VERSION 5.7 ;
BUSBITCHARS "[]" ;
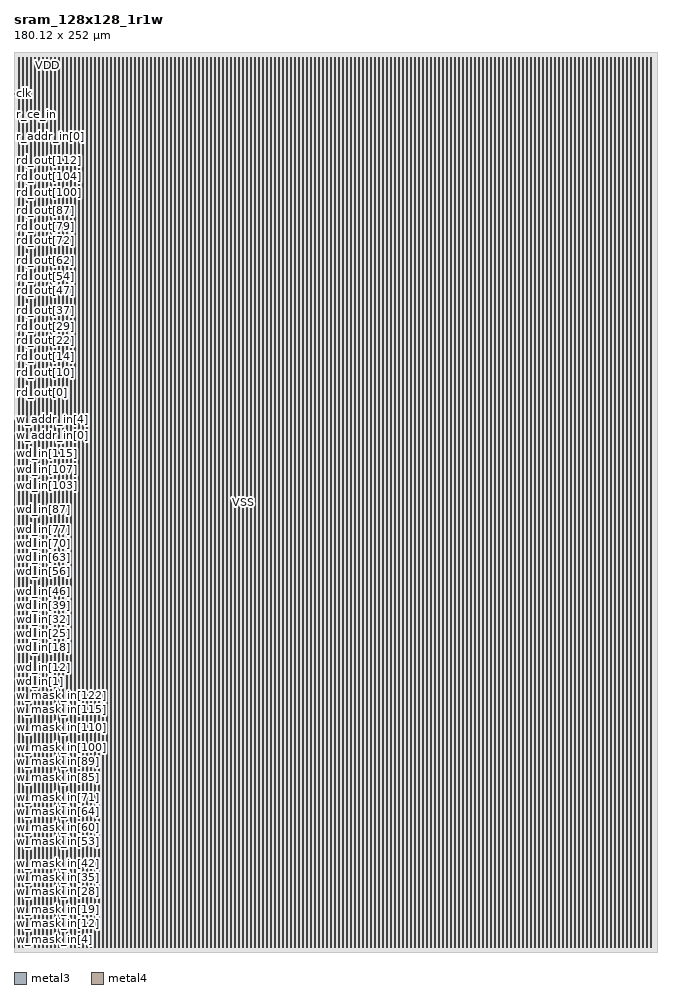
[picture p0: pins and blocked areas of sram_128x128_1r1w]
MACRO sram_128x128_1r1w
  FOREIGN sram_128x128_1r1w 0 0 ;
  SYMMETRY X Y R90 ;
  SIZE 180.120 BY 252.000 ;
  CLASS BLOCK ;
  PIN w_mask_in[0]
    DIRECTION INPUT ;
    USE SIGNAL ;
    SHAPE ABUTMENT ;
    PORT
      LAYER metal3 ;
      RECT 0.000 1.365 0.070 1.435 ;
    END
  END w_mask_in[0]
  PIN w_mask_in[1]
    DIRECTION INPUT ;
    USE SIGNAL ;
    SHAPE ABUTMENT ;
    PORT
      LAYER metal3 ;
      RECT 0.000 1.925 0.070 1.995 ;
    END
  END w_mask_in[1]
  PIN w_mask_in[2]
    DIRECTION INPUT ;
    USE SIGNAL ;
    SHAPE ABUTMENT ;
    PORT
      LAYER metal3 ;
      RECT 0.000 2.485 0.070 2.555 ;
    END
  END w_mask_in[2]
  PIN w_mask_in[3]
    DIRECTION INPUT ;
    USE SIGNAL ;
    SHAPE ABUTMENT ;
    PORT
      LAYER metal3 ;
      RECT 0.000 3.045 0.070 3.115 ;
    END
  END w_mask_in[3]
  PIN w_mask_in[4]
    DIRECTION INPUT ;
    USE SIGNAL ;
    SHAPE ABUTMENT ;
    PORT
      LAYER metal3 ;
      RECT 0.000 3.605 0.070 3.675 ;
    END
  END w_mask_in[4]
  PIN w_mask_in[5]
    DIRECTION INPUT ;
    USE SIGNAL ;
    SHAPE ABUTMENT ;
    PORT
      LAYER metal3 ;
      RECT 0.000 4.165 0.070 4.235 ;
    END
  END w_mask_in[5]
  PIN w_mask_in[6]
    DIRECTION INPUT ;
    USE SIGNAL ;
    SHAPE ABUTMENT ;
    PORT
      LAYER metal3 ;
      RECT 0.000 4.725 0.070 4.795 ;
    END
  END w_mask_in[6]
  PIN w_mask_in[7]
    DIRECTION INPUT ;
    USE SIGNAL ;
    SHAPE ABUTMENT ;
    PORT
      LAYER metal3 ;
      RECT 0.000 5.285 0.070 5.355 ;
    END
  END w_mask_in[7]
  PIN w_mask_in[8]
    DIRECTION INPUT ;
    USE SIGNAL ;
    SHAPE ABUTMENT ;
    PORT
      LAYER metal3 ;
      RECT 0.000 5.845 0.070 5.915 ;
    END
  END w_mask_in[8]
  PIN w_mask_in[9]
    DIRECTION INPUT ;
    USE SIGNAL ;
    SHAPE ABUTMENT ;
    PORT
      LAYER metal3 ;
      RECT 0.000 6.405 0.070 6.475 ;
    END
  END w_mask_in[9]
  PIN w_mask_in[10]
    DIRECTION INPUT ;
    USE SIGNAL ;
    SHAPE ABUTMENT ;
    PORT
      LAYER metal3 ;
      RECT 0.000 6.965 0.070 7.035 ;
    END
  END w_mask_in[10]
  PIN w_mask_in[11]
    DIRECTION INPUT ;
    USE SIGNAL ;
    SHAPE ABUTMENT ;
    PORT
      LAYER metal3 ;
      RECT 0.000 7.525 0.070 7.595 ;
    END
  END w_mask_in[11]
  PIN w_mask_in[12]
    DIRECTION INPUT ;
    USE SIGNAL ;
    SHAPE ABUTMENT ;
    PORT
      LAYER metal3 ;
      RECT 0.000 8.085 0.070 8.155 ;
    END
  END w_mask_in[12]
  PIN w_mask_in[13]
    DIRECTION INPUT ;
    USE SIGNAL ;
    SHAPE ABUTMENT ;
    PORT
      LAYER metal3 ;
      RECT 0.000 8.645 0.070 8.715 ;
    END
  END w_mask_in[13]
  PIN w_mask_in[14]
    DIRECTION INPUT ;
    USE SIGNAL ;
    SHAPE ABUTMENT ;
    PORT
      LAYER metal3 ;
      RECT 0.000 9.205 0.070 9.275 ;
    END
  END w_mask_in[14]
  PIN w_mask_in[15]
    DIRECTION INPUT ;
    USE SIGNAL ;
    SHAPE ABUTMENT ;
    PORT
      LAYER metal3 ;
      RECT 0.000 9.765 0.070 9.835 ;
    END
  END w_mask_in[15]
  PIN w_mask_in[16]
    DIRECTION INPUT ;
    USE SIGNAL ;
    SHAPE ABUTMENT ;
    PORT
      LAYER metal3 ;
      RECT 0.000 10.325 0.070 10.395 ;
    END
  END w_mask_in[16]
  PIN w_mask_in[17]
    DIRECTION INPUT ;
    USE SIGNAL ;
    SHAPE ABUTMENT ;
    PORT
      LAYER metal3 ;
      RECT 0.000 10.885 0.070 10.955 ;
    END
  END w_mask_in[17]
  PIN w_mask_in[18]
    DIRECTION INPUT ;
    USE SIGNAL ;
    SHAPE ABUTMENT ;
    PORT
      LAYER metal3 ;
      RECT 0.000 11.445 0.070 11.515 ;
    END
  END w_mask_in[18]
  PIN w_mask_in[19]
    DIRECTION INPUT ;
    USE SIGNAL ;
    SHAPE ABUTMENT ;
    PORT
      LAYER metal3 ;
      RECT 0.000 12.005 0.070 12.075 ;
    END
  END w_mask_in[19]
  PIN w_mask_in[20]
    DIRECTION INPUT ;
    USE SIGNAL ;
    SHAPE ABUTMENT ;
    PORT
      LAYER metal3 ;
      RECT 0.000 12.565 0.070 12.635 ;
    END
  END w_mask_in[20]
  PIN w_mask_in[21]
    DIRECTION INPUT ;
    USE SIGNAL ;
    SHAPE ABUTMENT ;
    PORT
      LAYER metal3 ;
      RECT 0.000 13.125 0.070 13.195 ;
    END
  END w_mask_in[21]
  PIN w_mask_in[22]
    DIRECTION INPUT ;
    USE SIGNAL ;
    SHAPE ABUTMENT ;
    PORT
      LAYER metal3 ;
      RECT 0.000 13.685 0.070 13.755 ;
    END
  END w_mask_in[22]
  PIN w_mask_in[23]
    DIRECTION INPUT ;
    USE SIGNAL ;
    SHAPE ABUTMENT ;
    PORT
      LAYER metal3 ;
      RECT 0.000 14.245 0.070 14.315 ;
    END
  END w_mask_in[23]
  PIN w_mask_in[24]
    DIRECTION INPUT ;
    USE SIGNAL ;
    SHAPE ABUTMENT ;
    PORT
      LAYER metal3 ;
      RECT 0.000 14.805 0.070 14.875 ;
    END
  END w_mask_in[24]
  PIN w_mask_in[25]
    DIRECTION INPUT ;
    USE SIGNAL ;
    SHAPE ABUTMENT ;
    PORT
      LAYER metal3 ;
      RECT 0.000 15.365 0.070 15.435 ;
    END
  END w_mask_in[25]
  PIN w_mask_in[26]
    DIRECTION INPUT ;
    USE SIGNAL ;
    SHAPE ABUTMENT ;
    PORT
      LAYER metal3 ;
      RECT 0.000 15.925 0.070 15.995 ;
    END
  END w_mask_in[26]
  PIN w_mask_in[27]
    DIRECTION INPUT ;
    USE SIGNAL ;
    SHAPE ABUTMENT ;
    PORT
      LAYER metal3 ;
      RECT 0.000 16.485 0.070 16.555 ;
    END
  END w_mask_in[27]
  PIN w_mask_in[28]
    DIRECTION INPUT ;
    USE SIGNAL ;
    SHAPE ABUTMENT ;
    PORT
      LAYER metal3 ;
      RECT 0.000 17.045 0.070 17.115 ;
    END
  END w_mask_in[28]
  PIN w_mask_in[29]
    DIRECTION INPUT ;
    USE SIGNAL ;
    SHAPE ABUTMENT ;
    PORT
      LAYER metal3 ;
      RECT 0.000 17.605 0.070 17.675 ;
    END
  END w_mask_in[29]
  PIN w_mask_in[30]
    DIRECTION INPUT ;
    USE SIGNAL ;
    SHAPE ABUTMENT ;
    PORT
      LAYER metal3 ;
      RECT 0.000 18.165 0.070 18.235 ;
    END
  END w_mask_in[30]
  PIN w_mask_in[31]
    DIRECTION INPUT ;
    USE SIGNAL ;
    SHAPE ABUTMENT ;
    PORT
      LAYER metal3 ;
      RECT 0.000 18.725 0.070 18.795 ;
    END
  END w_mask_in[31]
  PIN w_mask_in[32]
    DIRECTION INPUT ;
    USE SIGNAL ;
    SHAPE ABUTMENT ;
    PORT
      LAYER metal3 ;
      RECT 0.000 19.285 0.070 19.355 ;
    END
  END w_mask_in[32]
  PIN w_mask_in[33]
    DIRECTION INPUT ;
    USE SIGNAL ;
    SHAPE ABUTMENT ;
    PORT
      LAYER metal3 ;
      RECT 0.000 19.845 0.070 19.915 ;
    END
  END w_mask_in[33]
  PIN w_mask_in[34]
    DIRECTION INPUT ;
    USE SIGNAL ;
    SHAPE ABUTMENT ;
    PORT
      LAYER metal3 ;
      RECT 0.000 20.405 0.070 20.475 ;
    END
  END w_mask_in[34]
  PIN w_mask_in[35]
    DIRECTION INPUT ;
    USE SIGNAL ;
    SHAPE ABUTMENT ;
    PORT
      LAYER metal3 ;
      RECT 0.000 20.965 0.070 21.035 ;
    END
  END w_mask_in[35]
  PIN w_mask_in[36]
    DIRECTION INPUT ;
    USE SIGNAL ;
    SHAPE ABUTMENT ;
    PORT
      LAYER metal3 ;
      RECT 0.000 21.525 0.070 21.595 ;
    END
  END w_mask_in[36]
  PIN w_mask_in[37]
    DIRECTION INPUT ;
    USE SIGNAL ;
    SHAPE ABUTMENT ;
    PORT
      LAYER metal3 ;
      RECT 0.000 22.085 0.070 22.155 ;
    END
  END w_mask_in[37]
  PIN w_mask_in[38]
    DIRECTION INPUT ;
    USE SIGNAL ;
    SHAPE ABUTMENT ;
    PORT
      LAYER metal3 ;
      RECT 0.000 22.645 0.070 22.715 ;
    END
  END w_mask_in[38]
  PIN w_mask_in[39]
    DIRECTION INPUT ;
    USE SIGNAL ;
    SHAPE ABUTMENT ;
    PORT
      LAYER metal3 ;
      RECT 0.000 23.205 0.070 23.275 ;
    END
  END w_mask_in[39]
  PIN w_mask_in[40]
    DIRECTION INPUT ;
    USE SIGNAL ;
    SHAPE ABUTMENT ;
    PORT
      LAYER metal3 ;
      RECT 0.000 23.765 0.070 23.835 ;
    END
  END w_mask_in[40]
  PIN w_mask_in[41]
    DIRECTION INPUT ;
    USE SIGNAL ;
    SHAPE ABUTMENT ;
    PORT
      LAYER metal3 ;
      RECT 0.000 24.325 0.070 24.395 ;
    END
  END w_mask_in[41]
  PIN w_mask_in[42]
    DIRECTION INPUT ;
    USE SIGNAL ;
    SHAPE ABUTMENT ;
    PORT
      LAYER metal3 ;
      RECT 0.000 24.885 0.070 24.955 ;
    END
  END w_mask_in[42]
  PIN w_mask_in[43]
    DIRECTION INPUT ;
    USE SIGNAL ;
    SHAPE ABUTMENT ;
    PORT
      LAYER metal3 ;
      RECT 0.000 25.445 0.070 25.515 ;
    END
  END w_mask_in[43]
  PIN w_mask_in[44]
    DIRECTION INPUT ;
    USE SIGNAL ;
    SHAPE ABUTMENT ;
    PORT
      LAYER metal3 ;
      RECT 0.000 26.005 0.070 26.075 ;
    END
  END w_mask_in[44]
  PIN w_mask_in[45]
    DIRECTION INPUT ;
    USE SIGNAL ;
    SHAPE ABUTMENT ;
    PORT
      LAYER metal3 ;
      RECT 0.000 26.565 0.070 26.635 ;
    END
  END w_mask_in[45]
  PIN w_mask_in[46]
    DIRECTION INPUT ;
    USE SIGNAL ;
    SHAPE ABUTMENT ;
    PORT
      LAYER metal3 ;
      RECT 0.000 27.125 0.070 27.195 ;
    END
  END w_mask_in[46]
  PIN w_mask_in[47]
    DIRECTION INPUT ;
    USE SIGNAL ;
    SHAPE ABUTMENT ;
    PORT
      LAYER metal3 ;
      RECT 0.000 27.685 0.070 27.755 ;
    END
  END w_mask_in[47]
  PIN w_mask_in[48]
    DIRECTION INPUT ;
    USE SIGNAL ;
    SHAPE ABUTMENT ;
    PORT
      LAYER metal3 ;
      RECT 0.000 28.245 0.070 28.315 ;
    END
  END w_mask_in[48]
  PIN w_mask_in[49]
    DIRECTION INPUT ;
    USE SIGNAL ;
    SHAPE ABUTMENT ;
    PORT
      LAYER metal3 ;
      RECT 0.000 28.805 0.070 28.875 ;
    END
  END w_mask_in[49]
  PIN w_mask_in[50]
    DIRECTION INPUT ;
    USE SIGNAL ;
    SHAPE ABUTMENT ;
    PORT
      LAYER metal3 ;
      RECT 0.000 29.365 0.070 29.435 ;
    END
  END w_mask_in[50]
  PIN w_mask_in[51]
    DIRECTION INPUT ;
    USE SIGNAL ;
    SHAPE ABUTMENT ;
    PORT
      LAYER metal3 ;
      RECT 0.000 29.925 0.070 29.995 ;
    END
  END w_mask_in[51]
  PIN w_mask_in[52]
    DIRECTION INPUT ;
    USE SIGNAL ;
    SHAPE ABUTMENT ;
    PORT
      LAYER metal3 ;
      RECT 0.000 30.485 0.070 30.555 ;
    END
  END w_mask_in[52]
  PIN w_mask_in[53]
    DIRECTION INPUT ;
    USE SIGNAL ;
    SHAPE ABUTMENT ;
    PORT
      LAYER metal3 ;
      RECT 0.000 31.045 0.070 31.115 ;
    END
  END w_mask_in[53]
  PIN w_mask_in[54]
    DIRECTION INPUT ;
    USE SIGNAL ;
    SHAPE ABUTMENT ;
    PORT
      LAYER metal3 ;
      RECT 0.000 31.605 0.070 31.675 ;
    END
  END w_mask_in[54]
  PIN w_mask_in[55]
    DIRECTION INPUT ;
    USE SIGNAL ;
    SHAPE ABUTMENT ;
    PORT
      LAYER metal3 ;
      RECT 0.000 32.165 0.070 32.235 ;
    END
  END w_mask_in[55]
  PIN w_mask_in[56]
    DIRECTION INPUT ;
    USE SIGNAL ;
    SHAPE ABUTMENT ;
    PORT
      LAYER metal3 ;
      RECT 0.000 32.725 0.070 32.795 ;
    END
  END w_mask_in[56]
  PIN w_mask_in[57]
    DIRECTION INPUT ;
    USE SIGNAL ;
    SHAPE ABUTMENT ;
    PORT
      LAYER metal3 ;
      RECT 0.000 33.285 0.070 33.355 ;
    END
  END w_mask_in[57]
  PIN w_mask_in[58]
    DIRECTION INPUT ;
    USE SIGNAL ;
    SHAPE ABUTMENT ;
    PORT
      LAYER metal3 ;
      RECT 0.000 33.845 0.070 33.915 ;
    END
  END w_mask_in[58]
  PIN w_mask_in[59]
    DIRECTION INPUT ;
    USE SIGNAL ;
    SHAPE ABUTMENT ;
    PORT
      LAYER metal3 ;
      RECT 0.000 34.405 0.070 34.475 ;
    END
  END w_mask_in[59]
  PIN w_mask_in[60]
    DIRECTION INPUT ;
    USE SIGNAL ;
    SHAPE ABUTMENT ;
    PORT
      LAYER metal3 ;
      RECT 0.000 34.965 0.070 35.035 ;
    END
  END w_mask_in[60]
  PIN w_mask_in[61]
    DIRECTION INPUT ;
    USE SIGNAL ;
    SHAPE ABUTMENT ;
    PORT
      LAYER metal3 ;
      RECT 0.000 35.525 0.070 35.595 ;
    END
  END w_mask_in[61]
  PIN w_mask_in[62]
    DIRECTION INPUT ;
    USE SIGNAL ;
    SHAPE ABUTMENT ;
    PORT
      LAYER metal3 ;
      RECT 0.000 36.085 0.070 36.155 ;
    END
  END w_mask_in[62]
  PIN w_mask_in[63]
    DIRECTION INPUT ;
    USE SIGNAL ;
    SHAPE ABUTMENT ;
    PORT
      LAYER metal3 ;
      RECT 0.000 36.645 0.070 36.715 ;
    END
  END w_mask_in[63]
  PIN w_mask_in[64]
    DIRECTION INPUT ;
    USE SIGNAL ;
    SHAPE ABUTMENT ;
    PORT
      LAYER metal3 ;
      RECT 0.000 37.205 0.070 37.275 ;
    END
  END w_mask_in[64]
  PIN w_mask_in[65]
    DIRECTION INPUT ;
    USE SIGNAL ;
    SHAPE ABUTMENT ;
    PORT
      LAYER metal3 ;
      RECT 0.000 37.765 0.070 37.835 ;
    END
  END w_mask_in[65]
  PIN w_mask_in[66]
    DIRECTION INPUT ;
    USE SIGNAL ;
    SHAPE ABUTMENT ;
    PORT
      LAYER metal3 ;
      RECT 0.000 38.325 0.070 38.395 ;
    END
  END w_mask_in[66]
  PIN w_mask_in[67]
    DIRECTION INPUT ;
    USE SIGNAL ;
    SHAPE ABUTMENT ;
    PORT
      LAYER metal3 ;
      RECT 0.000 38.885 0.070 38.955 ;
    END
  END w_mask_in[67]
  PIN w_mask_in[68]
    DIRECTION INPUT ;
    USE SIGNAL ;
    SHAPE ABUTMENT ;
    PORT
      LAYER metal3 ;
      RECT 0.000 39.445 0.070 39.515 ;
    END
  END w_mask_in[68]
  PIN w_mask_in[69]
    DIRECTION INPUT ;
    USE SIGNAL ;
    SHAPE ABUTMENT ;
    PORT
      LAYER metal3 ;
      RECT 0.000 40.005 0.070 40.075 ;
    END
  END w_mask_in[69]
  PIN w_mask_in[70]
    DIRECTION INPUT ;
    USE SIGNAL ;
    SHAPE ABUTMENT ;
    PORT
      LAYER metal3 ;
      RECT 0.000 40.565 0.070 40.635 ;
    END
  END w_mask_in[70]
  PIN w_mask_in[71]
    DIRECTION INPUT ;
    USE SIGNAL ;
    SHAPE ABUTMENT ;
    PORT
      LAYER metal3 ;
      RECT 0.000 41.125 0.070 41.195 ;
    END
  END w_mask_in[71]
  PIN w_mask_in[72]
    DIRECTION INPUT ;
    USE SIGNAL ;
    SHAPE ABUTMENT ;
    PORT
      LAYER metal3 ;
      RECT 0.000 41.685 0.070 41.755 ;
    END
  END w_mask_in[72]
  PIN w_mask_in[73]
    DIRECTION INPUT ;
    USE SIGNAL ;
    SHAPE ABUTMENT ;
    PORT
      LAYER metal3 ;
      RECT 0.000 42.245 0.070 42.315 ;
    END
  END w_mask_in[73]
  PIN w_mask_in[74]
    DIRECTION INPUT ;
    USE SIGNAL ;
    SHAPE ABUTMENT ;
    PORT
      LAYER metal3 ;
      RECT 0.000 42.805 0.070 42.875 ;
    END
  END w_mask_in[74]
  PIN w_mask_in[75]
    DIRECTION INPUT ;
    USE SIGNAL ;
    SHAPE ABUTMENT ;
    PORT
      LAYER metal3 ;
      RECT 0.000 43.365 0.070 43.435 ;
    END
  END w_mask_in[75]
  PIN w_mask_in[76]
    DIRECTION INPUT ;
    USE SIGNAL ;
    SHAPE ABUTMENT ;
    PORT
      LAYER metal3 ;
      RECT 0.000 43.925 0.070 43.995 ;
    END
  END w_mask_in[76]
  PIN w_mask_in[77]
    DIRECTION INPUT ;
    USE SIGNAL ;
    SHAPE ABUTMENT ;
    PORT
      LAYER metal3 ;
      RECT 0.000 44.485 0.070 44.555 ;
    END
  END w_mask_in[77]
  PIN w_mask_in[78]
    DIRECTION INPUT ;
    USE SIGNAL ;
    SHAPE ABUTMENT ;
    PORT
      LAYER metal3 ;
      RECT 0.000 45.045 0.070 45.115 ;
    END
  END w_mask_in[78]
  PIN w_mask_in[79]
    DIRECTION INPUT ;
    USE SIGNAL ;
    SHAPE ABUTMENT ;
    PORT
      LAYER metal3 ;
      RECT 0.000 45.605 0.070 45.675 ;
    END
  END w_mask_in[79]
  PIN w_mask_in[80]
    DIRECTION INPUT ;
    USE SIGNAL ;
    SHAPE ABUTMENT ;
    PORT
      LAYER metal3 ;
      RECT 0.000 46.165 0.070 46.235 ;
    END
  END w_mask_in[80]
  PIN w_mask_in[81]
    DIRECTION INPUT ;
    USE SIGNAL ;
    SHAPE ABUTMENT ;
    PORT
      LAYER metal3 ;
      RECT 0.000 46.725 0.070 46.795 ;
    END
  END w_mask_in[81]
  PIN w_mask_in[82]
    DIRECTION INPUT ;
    USE SIGNAL ;
    SHAPE ABUTMENT ;
    PORT
      LAYER metal3 ;
      RECT 0.000 47.285 0.070 47.355 ;
    END
  END w_mask_in[82]
  PIN w_mask_in[83]
    DIRECTION INPUT ;
    USE SIGNAL ;
    SHAPE ABUTMENT ;
    PORT
      LAYER metal3 ;
      RECT 0.000 47.845 0.070 47.915 ;
    END
  END w_mask_in[83]
  PIN w_mask_in[84]
    DIRECTION INPUT ;
    USE SIGNAL ;
    SHAPE ABUTMENT ;
    PORT
      LAYER metal3 ;
      RECT 0.000 48.405 0.070 48.475 ;
    END
  END w_mask_in[84]
  PIN w_mask_in[85]
    DIRECTION INPUT ;
    USE SIGNAL ;
    SHAPE ABUTMENT ;
    PORT
      LAYER metal3 ;
      RECT 0.000 48.965 0.070 49.035 ;
    END
  END w_mask_in[85]
  PIN w_mask_in[86]
    DIRECTION INPUT ;
    USE SIGNAL ;
    SHAPE ABUTMENT ;
    PORT
      LAYER metal3 ;
      RECT 0.000 49.525 0.070 49.595 ;
    END
  END w_mask_in[86]
  PIN w_mask_in[87]
    DIRECTION INPUT ;
    USE SIGNAL ;
    SHAPE ABUTMENT ;
    PORT
      LAYER metal3 ;
      RECT 0.000 50.085 0.070 50.155 ;
    END
  END w_mask_in[87]
  PIN w_mask_in[88]
    DIRECTION INPUT ;
    USE SIGNAL ;
    SHAPE ABUTMENT ;
    PORT
      LAYER metal3 ;
      RECT 0.000 50.645 0.070 50.715 ;
    END
  END w_mask_in[88]
  PIN w_mask_in[89]
    DIRECTION INPUT ;
    USE SIGNAL ;
    SHAPE ABUTMENT ;
    PORT
      LAYER metal3 ;
      RECT 0.000 51.205 0.070 51.275 ;
    END
  END w_mask_in[89]
  PIN w_mask_in[90]
    DIRECTION INPUT ;
    USE SIGNAL ;
    SHAPE ABUTMENT ;
    PORT
      LAYER metal3 ;
      RECT 0.000 51.765 0.070 51.835 ;
    END
  END w_mask_in[90]
  PIN w_mask_in[91]
    DIRECTION INPUT ;
    USE SIGNAL ;
    SHAPE ABUTMENT ;
    PORT
      LAYER metal3 ;
      RECT 0.000 52.325 0.070 52.395 ;
    END
  END w_mask_in[91]
  PIN w_mask_in[92]
    DIRECTION INPUT ;
    USE SIGNAL ;
    SHAPE ABUTMENT ;
    PORT
      LAYER metal3 ;
      RECT 0.000 52.885 0.070 52.955 ;
    END
  END w_mask_in[92]
  PIN w_mask_in[93]
    DIRECTION INPUT ;
    USE SIGNAL ;
    SHAPE ABUTMENT ;
    PORT
      LAYER metal3 ;
      RECT 0.000 53.445 0.070 53.515 ;
    END
  END w_mask_in[93]
  PIN w_mask_in[94]
    DIRECTION INPUT ;
    USE SIGNAL ;
    SHAPE ABUTMENT ;
    PORT
      LAYER metal3 ;
      RECT 0.000 54.005 0.070 54.075 ;
    END
  END w_mask_in[94]
  PIN w_mask_in[95]
    DIRECTION INPUT ;
    USE SIGNAL ;
    SHAPE ABUTMENT ;
    PORT
      LAYER metal3 ;
      RECT 0.000 54.565 0.070 54.635 ;
    END
  END w_mask_in[95]
  PIN w_mask_in[96]
    DIRECTION INPUT ;
    USE SIGNAL ;
    SHAPE ABUTMENT ;
    PORT
      LAYER metal3 ;
      RECT 0.000 55.125 0.070 55.195 ;
    END
  END w_mask_in[96]
  PIN w_mask_in[97]
    DIRECTION INPUT ;
    USE SIGNAL ;
    SHAPE ABUTMENT ;
    PORT
      LAYER metal3 ;
      RECT 0.000 55.685 0.070 55.755 ;
    END
  END w_mask_in[97]
  PIN w_mask_in[98]
    DIRECTION INPUT ;
    USE SIGNAL ;
    SHAPE ABUTMENT ;
    PORT
      LAYER metal3 ;
      RECT 0.000 56.245 0.070 56.315 ;
    END
  END w_mask_in[98]
  PIN w_mask_in[99]
    DIRECTION INPUT ;
    USE SIGNAL ;
    SHAPE ABUTMENT ;
    PORT
      LAYER metal3 ;
      RECT 0.000 56.805 0.070 56.875 ;
    END
  END w_mask_in[99]
  PIN w_mask_in[100]
    DIRECTION INPUT ;
    USE SIGNAL ;
    SHAPE ABUTMENT ;
    PORT
      LAYER metal3 ;
      RECT 0.000 57.365 0.070 57.435 ;
    END
  END w_mask_in[100]
  PIN w_mask_in[101]
    DIRECTION INPUT ;
    USE SIGNAL ;
    SHAPE ABUTMENT ;
    PORT
      LAYER metal3 ;
      RECT 0.000 57.925 0.070 57.995 ;
    END
  END w_mask_in[101]
  PIN w_mask_in[102]
    DIRECTION INPUT ;
    USE SIGNAL ;
    SHAPE ABUTMENT ;
    PORT
      LAYER metal3 ;
      RECT 0.000 58.485 0.070 58.555 ;
    END
  END w_mask_in[102]
  PIN w_mask_in[103]
    DIRECTION INPUT ;
    USE SIGNAL ;
    SHAPE ABUTMENT ;
    PORT
      LAYER metal3 ;
      RECT 0.000 59.045 0.070 59.115 ;
    END
  END w_mask_in[103]
  PIN w_mask_in[104]
    DIRECTION INPUT ;
    USE SIGNAL ;
    SHAPE ABUTMENT ;
    PORT
      LAYER metal3 ;
      RECT 0.000 59.605 0.070 59.675 ;
    END
  END w_mask_in[104]
  PIN w_mask_in[105]
    DIRECTION INPUT ;
    USE SIGNAL ;
    SHAPE ABUTMENT ;
    PORT
      LAYER metal3 ;
      RECT 0.000 60.165 0.070 60.235 ;
    END
  END w_mask_in[105]
  PIN w_mask_in[106]
    DIRECTION INPUT ;
    USE SIGNAL ;
    SHAPE ABUTMENT ;
    PORT
      LAYER metal3 ;
      RECT 0.000 60.725 0.070 60.795 ;
    END
  END w_mask_in[106]
  PIN w_mask_in[107]
    DIRECTION INPUT ;
    USE SIGNAL ;
    SHAPE ABUTMENT ;
    PORT
      LAYER metal3 ;
      RECT 0.000 61.285 0.070 61.355 ;
    END
  END w_mask_in[107]
  PIN w_mask_in[108]
    DIRECTION INPUT ;
    USE SIGNAL ;
    SHAPE ABUTMENT ;
    PORT
      LAYER metal3 ;
      RECT 0.000 61.845 0.070 61.915 ;
    END
  END w_mask_in[108]
  PIN w_mask_in[109]
    DIRECTION INPUT ;
    USE SIGNAL ;
    SHAPE ABUTMENT ;
    PORT
      LAYER metal3 ;
      RECT 0.000 62.405 0.070 62.475 ;
    END
  END w_mask_in[109]
  PIN w_mask_in[110]
    DIRECTION INPUT ;
    USE SIGNAL ;
    SHAPE ABUTMENT ;
    PORT
      LAYER metal3 ;
      RECT 0.000 62.965 0.070 63.035 ;
    END
  END w_mask_in[110]
  PIN w_mask_in[111]
    DIRECTION INPUT ;
    USE SIGNAL ;
    SHAPE ABUTMENT ;
    PORT
      LAYER metal3 ;
      RECT 0.000 63.525 0.070 63.595 ;
    END
  END w_mask_in[111]
  PIN w_mask_in[112]
    DIRECTION INPUT ;
    USE SIGNAL ;
    SHAPE ABUTMENT ;
    PORT
      LAYER metal3 ;
      RECT 0.000 64.085 0.070 64.155 ;
    END
  END w_mask_in[112]
  PIN w_mask_in[113]
    DIRECTION INPUT ;
    USE SIGNAL ;
    SHAPE ABUTMENT ;
    PORT
      LAYER metal3 ;
      RECT 0.000 64.645 0.070 64.715 ;
    END
  END w_mask_in[113]
  PIN w_mask_in[114]
    DIRECTION INPUT ;
    USE SIGNAL ;
    SHAPE ABUTMENT ;
    PORT
      LAYER metal3 ;
      RECT 0.000 65.205 0.070 65.275 ;
    END
  END w_mask_in[114]
  PIN w_mask_in[115]
    DIRECTION INPUT ;
    USE SIGNAL ;
    SHAPE ABUTMENT ;
    PORT
      LAYER metal3 ;
      RECT 0.000 65.765 0.070 65.835 ;
    END
  END w_mask_in[115]
  PIN w_mask_in[116]
    DIRECTION INPUT ;
    USE SIGNAL ;
    SHAPE ABUTMENT ;
    PORT
      LAYER metal3 ;
      RECT 0.000 66.325 0.070 66.395 ;
    END
  END w_mask_in[116]
  PIN w_mask_in[117]
    DIRECTION INPUT ;
    USE SIGNAL ;
    SHAPE ABUTMENT ;
    PORT
      LAYER metal3 ;
      RECT 0.000 66.885 0.070 66.955 ;
    END
  END w_mask_in[117]
  PIN w_mask_in[118]
    DIRECTION INPUT ;
    USE SIGNAL ;
    SHAPE ABUTMENT ;
    PORT
      LAYER metal3 ;
      RECT 0.000 67.445 0.070 67.515 ;
    END
  END w_mask_in[118]
  PIN w_mask_in[119]
    DIRECTION INPUT ;
    USE SIGNAL ;
    SHAPE ABUTMENT ;
    PORT
      LAYER metal3 ;
      RECT 0.000 68.005 0.070 68.075 ;
    END
  END w_mask_in[119]
  PIN w_mask_in[120]
    DIRECTION INPUT ;
    USE SIGNAL ;
    SHAPE ABUTMENT ;
    PORT
      LAYER metal3 ;
      RECT 0.000 68.565 0.070 68.635 ;
    END
  END w_mask_in[120]
  PIN w_mask_in[121]
    DIRECTION INPUT ;
    USE SIGNAL ;
    SHAPE ABUTMENT ;
    PORT
      LAYER metal3 ;
      RECT 0.000 69.125 0.070 69.195 ;
    END
  END w_mask_in[121]
  PIN w_mask_in[122]
    DIRECTION INPUT ;
    USE SIGNAL ;
    SHAPE ABUTMENT ;
    PORT
      LAYER metal3 ;
      RECT 0.000 69.685 0.070 69.755 ;
    END
  END w_mask_in[122]
  PIN w_mask_in[123]
    DIRECTION INPUT ;
    USE SIGNAL ;
    SHAPE ABUTMENT ;
    PORT
      LAYER metal3 ;
      RECT 0.000 70.245 0.070 70.315 ;
    END
  END w_mask_in[123]
  PIN w_mask_in[124]
    DIRECTION INPUT ;
    USE SIGNAL ;
    SHAPE ABUTMENT ;
    PORT
      LAYER metal3 ;
      RECT 0.000 70.805 0.070 70.875 ;
    END
  END w_mask_in[124]
  PIN w_mask_in[125]
    DIRECTION INPUT ;
    USE SIGNAL ;
    SHAPE ABUTMENT ;
    PORT
      LAYER metal3 ;
      RECT 0.000 71.365 0.070 71.435 ;
    END
  END w_mask_in[125]
  PIN w_mask_in[126]
    DIRECTION INPUT ;
    USE SIGNAL ;
    SHAPE ABUTMENT ;
    PORT
      LAYER metal3 ;
      RECT 0.000 71.925 0.070 71.995 ;
    END
  END w_mask_in[126]
  PIN w_mask_in[127]
    DIRECTION INPUT ;
    USE SIGNAL ;
    SHAPE ABUTMENT ;
    PORT
      LAYER metal3 ;
      RECT 0.000 72.485 0.070 72.555 ;
    END
  END w_mask_in[127]
  PIN wd_in[0]
    DIRECTION INPUT ;
    USE SIGNAL ;
    SHAPE ABUTMENT ;
    PORT
      LAYER metal3 ;
      RECT 0.000 73.045 0.070 73.115 ;
    END
  END wd_in[0]
  PIN wd_in[1]
    DIRECTION INPUT ;
    USE SIGNAL ;
    SHAPE ABUTMENT ;
    PORT
      LAYER metal3 ;
      RECT 0.000 73.605 0.070 73.675 ;
    END
  END wd_in[1]
  PIN wd_in[2]
    DIRECTION INPUT ;
    USE SIGNAL ;
    SHAPE ABUTMENT ;
    PORT
      LAYER metal3 ;
      RECT 0.000 74.165 0.070 74.235 ;
    END
  END wd_in[2]
  PIN wd_in[3]
    DIRECTION INPUT ;
    USE SIGNAL ;
    SHAPE ABUTMENT ;
    PORT
      LAYER metal3 ;
      RECT 0.000 74.725 0.070 74.795 ;
    END
  END wd_in[3]
  PIN wd_in[4]
    DIRECTION INPUT ;
    USE SIGNAL ;
    SHAPE ABUTMENT ;
    PORT
      LAYER metal3 ;
      RECT 0.000 75.285 0.070 75.355 ;
    END
  END wd_in[4]
  PIN wd_in[5]
    DIRECTION INPUT ;
    USE SIGNAL ;
    SHAPE ABUTMENT ;
    PORT
      LAYER metal3 ;
      RECT 0.000 75.845 0.070 75.915 ;
    END
  END wd_in[5]
  PIN wd_in[6]
    DIRECTION INPUT ;
    USE SIGNAL ;
    SHAPE ABUTMENT ;
    PORT
      LAYER metal3 ;
      RECT 0.000 76.405 0.070 76.475 ;
    END
  END wd_in[6]
  PIN wd_in[7]
    DIRECTION INPUT ;
    USE SIGNAL ;
    SHAPE ABUTMENT ;
    PORT
      LAYER metal3 ;
      RECT 0.000 76.965 0.070 77.035 ;
    END
  END wd_in[7]
  PIN wd_in[8]
    DIRECTION INPUT ;
    USE SIGNAL ;
    SHAPE ABUTMENT ;
    PORT
      LAYER metal3 ;
      RECT 0.000 77.525 0.070 77.595 ;
    END
  END wd_in[8]
  PIN wd_in[9]
    DIRECTION INPUT ;
    USE SIGNAL ;
    SHAPE ABUTMENT ;
    PORT
      LAYER metal3 ;
      RECT 0.000 78.085 0.070 78.155 ;
    END
  END wd_in[9]
  PIN wd_in[10]
    DIRECTION INPUT ;
    USE SIGNAL ;
    SHAPE ABUTMENT ;
    PORT
      LAYER metal3 ;
      RECT 0.000 78.645 0.070 78.715 ;
    END
  END wd_in[10]
  PIN wd_in[11]
    DIRECTION INPUT ;
    USE SIGNAL ;
    SHAPE ABUTMENT ;
    PORT
      LAYER metal3 ;
      RECT 0.000 79.205 0.070 79.275 ;
    END
  END wd_in[11]
  PIN wd_in[12]
    DIRECTION INPUT ;
    USE SIGNAL ;
    SHAPE ABUTMENT ;
    PORT
      LAYER metal3 ;
      RECT 0.000 79.765 0.070 79.835 ;
    END
  END wd_in[12]
  PIN wd_in[13]
    DIRECTION INPUT ;
    USE SIGNAL ;
    SHAPE ABUTMENT ;
    PORT
      LAYER metal3 ;
      RECT 0.000 80.325 0.070 80.395 ;
    END
  END wd_in[13]
  PIN wd_in[14]
    DIRECTION INPUT ;
    USE SIGNAL ;
    SHAPE ABUTMENT ;
    PORT
      LAYER metal3 ;
      RECT 0.000 80.885 0.070 80.955 ;
    END
  END wd_in[14]
  PIN wd_in[15]
    DIRECTION INPUT ;
    USE SIGNAL ;
    SHAPE ABUTMENT ;
    PORT
      LAYER metal3 ;
      RECT 0.000 81.445 0.070 81.515 ;
    END
  END wd_in[15]
  PIN wd_in[16]
    DIRECTION INPUT ;
    USE SIGNAL ;
    SHAPE ABUTMENT ;
    PORT
      LAYER metal3 ;
      RECT 0.000 82.005 0.070 82.075 ;
    END
  END wd_in[16]
  PIN wd_in[17]
    DIRECTION INPUT ;
    USE SIGNAL ;
    SHAPE ABUTMENT ;
    PORT
      LAYER metal3 ;
      RECT 0.000 82.565 0.070 82.635 ;
    END
  END wd_in[17]
  PIN wd_in[18]
    DIRECTION INPUT ;
    USE SIGNAL ;
    SHAPE ABUTMENT ;
    PORT
      LAYER metal3 ;
      RECT 0.000 83.125 0.070 83.195 ;
    END
  END wd_in[18]
  PIN wd_in[19]
    DIRECTION INPUT ;
    USE SIGNAL ;
    SHAPE ABUTMENT ;
    PORT
      LAYER metal3 ;
      RECT 0.000 83.685 0.070 83.755 ;
    END
  END wd_in[19]
  PIN wd_in[20]
    DIRECTION INPUT ;
    USE SIGNAL ;
    SHAPE ABUTMENT ;
    PORT
      LAYER metal3 ;
      RECT 0.000 84.245 0.070 84.315 ;
    END
  END wd_in[20]
  PIN wd_in[21]
    DIRECTION INPUT ;
    USE SIGNAL ;
    SHAPE ABUTMENT ;
    PORT
      LAYER metal3 ;
      RECT 0.000 84.805 0.070 84.875 ;
    END
  END wd_in[21]
  PIN wd_in[22]
    DIRECTION INPUT ;
    USE SIGNAL ;
    SHAPE ABUTMENT ;
    PORT
      LAYER metal3 ;
      RECT 0.000 85.365 0.070 85.435 ;
    END
  END wd_in[22]
  PIN wd_in[23]
    DIRECTION INPUT ;
    USE SIGNAL ;
    SHAPE ABUTMENT ;
    PORT
      LAYER metal3 ;
      RECT 0.000 85.925 0.070 85.995 ;
    END
  END wd_in[23]
  PIN wd_in[24]
    DIRECTION INPUT ;
    USE SIGNAL ;
    SHAPE ABUTMENT ;
    PORT
      LAYER metal3 ;
      RECT 0.000 86.485 0.070 86.555 ;
    END
  END wd_in[24]
  PIN wd_in[25]
    DIRECTION INPUT ;
    USE SIGNAL ;
    SHAPE ABUTMENT ;
    PORT
      LAYER metal3 ;
      RECT 0.000 87.045 0.070 87.115 ;
    END
  END wd_in[25]
  PIN wd_in[26]
    DIRECTION INPUT ;
    USE SIGNAL ;
    SHAPE ABUTMENT ;
    PORT
      LAYER metal3 ;
      RECT 0.000 87.605 0.070 87.675 ;
    END
  END wd_in[26]
  PIN wd_in[27]
    DIRECTION INPUT ;
    USE SIGNAL ;
    SHAPE ABUTMENT ;
    PORT
      LAYER metal3 ;
      RECT 0.000 88.165 0.070 88.235 ;
    END
  END wd_in[27]
  PIN wd_in[28]
    DIRECTION INPUT ;
    USE SIGNAL ;
    SHAPE ABUTMENT ;
    PORT
      LAYER metal3 ;
      RECT 0.000 88.725 0.070 88.795 ;
    END
  END wd_in[28]
  PIN wd_in[29]
    DIRECTION INPUT ;
    USE SIGNAL ;
    SHAPE ABUTMENT ;
    PORT
      LAYER metal3 ;
      RECT 0.000 89.285 0.070 89.355 ;
    END
  END wd_in[29]
  PIN wd_in[30]
    DIRECTION INPUT ;
    USE SIGNAL ;
    SHAPE ABUTMENT ;
    PORT
      LAYER metal3 ;
      RECT 0.000 89.845 0.070 89.915 ;
    END
  END wd_in[30]
  PIN wd_in[31]
    DIRECTION INPUT ;
    USE SIGNAL ;
    SHAPE ABUTMENT ;
    PORT
      LAYER metal3 ;
      RECT 0.000 90.405 0.070 90.475 ;
    END
  END wd_in[31]
  PIN wd_in[32]
    DIRECTION INPUT ;
    USE SIGNAL ;
    SHAPE ABUTMENT ;
    PORT
      LAYER metal3 ;
      RECT 0.000 90.965 0.070 91.035 ;
    END
  END wd_in[32]
  PIN wd_in[33]
    DIRECTION INPUT ;
    USE SIGNAL ;
    SHAPE ABUTMENT ;
    PORT
      LAYER metal3 ;
      RECT 0.000 91.525 0.070 91.595 ;
    END
  END wd_in[33]
  PIN wd_in[34]
    DIRECTION INPUT ;
    USE SIGNAL ;
    SHAPE ABUTMENT ;
    PORT
      LAYER metal3 ;
      RECT 0.000 92.085 0.070 92.155 ;
    END
  END wd_in[34]
  PIN wd_in[35]
    DIRECTION INPUT ;
    USE SIGNAL ;
    SHAPE ABUTMENT ;
    PORT
      LAYER metal3 ;
      RECT 0.000 92.645 0.070 92.715 ;
    END
  END wd_in[35]
  PIN wd_in[36]
    DIRECTION INPUT ;
    USE SIGNAL ;
    SHAPE ABUTMENT ;
    PORT
      LAYER metal3 ;
      RECT 0.000 93.205 0.070 93.275 ;
    END
  END wd_in[36]
  PIN wd_in[37]
    DIRECTION INPUT ;
    USE SIGNAL ;
    SHAPE ABUTMENT ;
    PORT
      LAYER metal3 ;
      RECT 0.000 93.765 0.070 93.835 ;
    END
  END wd_in[37]
  PIN wd_in[38]
    DIRECTION INPUT ;
    USE SIGNAL ;
    SHAPE ABUTMENT ;
    PORT
      LAYER metal3 ;
      RECT 0.000 94.325 0.070 94.395 ;
    END
  END wd_in[38]
  PIN wd_in[39]
    DIRECTION INPUT ;
    USE SIGNAL ;
    SHAPE ABUTMENT ;
    PORT
      LAYER metal3 ;
      RECT 0.000 94.885 0.070 94.955 ;
    END
  END wd_in[39]
  PIN wd_in[40]
    DIRECTION INPUT ;
    USE SIGNAL ;
    SHAPE ABUTMENT ;
    PORT
      LAYER metal3 ;
      RECT 0.000 95.445 0.070 95.515 ;
    END
  END wd_in[40]
  PIN wd_in[41]
    DIRECTION INPUT ;
    USE SIGNAL ;
    SHAPE ABUTMENT ;
    PORT
      LAYER metal3 ;
      RECT 0.000 96.005 0.070 96.075 ;
    END
  END wd_in[41]
  PIN wd_in[42]
    DIRECTION INPUT ;
    USE SIGNAL ;
    SHAPE ABUTMENT ;
    PORT
      LAYER metal3 ;
      RECT 0.000 96.565 0.070 96.635 ;
    END
  END wd_in[42]
  PIN wd_in[43]
    DIRECTION INPUT ;
    USE SIGNAL ;
    SHAPE ABUTMENT ;
    PORT
      LAYER metal3 ;
      RECT 0.000 97.125 0.070 97.195 ;
    END
  END wd_in[43]
  PIN wd_in[44]
    DIRECTION INPUT ;
    USE SIGNAL ;
    SHAPE ABUTMENT ;
    PORT
      LAYER metal3 ;
      RECT 0.000 97.685 0.070 97.755 ;
    END
  END wd_in[44]
  PIN wd_in[45]
    DIRECTION INPUT ;
    USE SIGNAL ;
    SHAPE ABUTMENT ;
    PORT
      LAYER metal3 ;
      RECT 0.000 98.245 0.070 98.315 ;
    END
  END wd_in[45]
  PIN wd_in[46]
    DIRECTION INPUT ;
    USE SIGNAL ;
    SHAPE ABUTMENT ;
    PORT
      LAYER metal3 ;
      RECT 0.000 98.805 0.070 98.875 ;
    END
  END wd_in[46]
  PIN wd_in[47]
    DIRECTION INPUT ;
    USE SIGNAL ;
    SHAPE ABUTMENT ;
    PORT
      LAYER metal3 ;
      RECT 0.000 99.365 0.070 99.435 ;
    END
  END wd_in[47]
  PIN wd_in[48]
    DIRECTION INPUT ;
    USE SIGNAL ;
    SHAPE ABUTMENT ;
    PORT
      LAYER metal3 ;
      RECT 0.000 99.925 0.070 99.995 ;
    END
  END wd_in[48]
  PIN wd_in[49]
    DIRECTION INPUT ;
    USE SIGNAL ;
    SHAPE ABUTMENT ;
    PORT
      LAYER metal3 ;
      RECT 0.000 100.485 0.070 100.555 ;
    END
  END wd_in[49]
  PIN wd_in[50]
    DIRECTION INPUT ;
    USE SIGNAL ;
    SHAPE ABUTMENT ;
    PORT
      LAYER metal3 ;
      RECT 0.000 101.045 0.070 101.115 ;
    END
  END wd_in[50]
  PIN wd_in[51]
    DIRECTION INPUT ;
    USE SIGNAL ;
    SHAPE ABUTMENT ;
    PORT
      LAYER metal3 ;
      RECT 0.000 101.605 0.070 101.675 ;
    END
  END wd_in[51]
  PIN wd_in[52]
    DIRECTION INPUT ;
    USE SIGNAL ;
    SHAPE ABUTMENT ;
    PORT
      LAYER metal3 ;
      RECT 0.000 102.165 0.070 102.235 ;
    END
  END wd_in[52]
  PIN wd_in[53]
    DIRECTION INPUT ;
    USE SIGNAL ;
    SHAPE ABUTMENT ;
    PORT
      LAYER metal3 ;
      RECT 0.000 102.725 0.070 102.795 ;
    END
  END wd_in[53]
  PIN wd_in[54]
    DIRECTION INPUT ;
    USE SIGNAL ;
    SHAPE ABUTMENT ;
    PORT
      LAYER metal3 ;
      RECT 0.000 103.285 0.070 103.355 ;
    END
  END wd_in[54]
  PIN wd_in[55]
    DIRECTION INPUT ;
    USE SIGNAL ;
    SHAPE ABUTMENT ;
    PORT
      LAYER metal3 ;
      RECT 0.000 103.845 0.070 103.915 ;
    END
  END wd_in[55]
  PIN wd_in[56]
    DIRECTION INPUT ;
    USE SIGNAL ;
    SHAPE ABUTMENT ;
    PORT
      LAYER metal3 ;
      RECT 0.000 104.405 0.070 104.475 ;
    END
  END wd_in[56]
  PIN wd_in[57]
    DIRECTION INPUT ;
    USE SIGNAL ;
    SHAPE ABUTMENT ;
    PORT
      LAYER metal3 ;
      RECT 0.000 104.965 0.070 105.035 ;
    END
  END wd_in[57]
  PIN wd_in[58]
    DIRECTION INPUT ;
    USE SIGNAL ;
    SHAPE ABUTMENT ;
    PORT
      LAYER metal3 ;
      RECT 0.000 105.525 0.070 105.595 ;
    END
  END wd_in[58]
  PIN wd_in[59]
    DIRECTION INPUT ;
    USE SIGNAL ;
    SHAPE ABUTMENT ;
    PORT
      LAYER metal3 ;
      RECT 0.000 106.085 0.070 106.155 ;
    END
  END wd_in[59]
  PIN wd_in[60]
    DIRECTION INPUT ;
    USE SIGNAL ;
    SHAPE ABUTMENT ;
    PORT
      LAYER metal3 ;
      RECT 0.000 106.645 0.070 106.715 ;
    END
  END wd_in[60]
  PIN wd_in[61]
    DIRECTION INPUT ;
    USE SIGNAL ;
    SHAPE ABUTMENT ;
    PORT
      LAYER metal3 ;
      RECT 0.000 107.205 0.070 107.275 ;
    END
  END wd_in[61]
  PIN wd_in[62]
    DIRECTION INPUT ;
    USE SIGNAL ;
    SHAPE ABUTMENT ;
    PORT
      LAYER metal3 ;
      RECT 0.000 107.765 0.070 107.835 ;
    END
  END wd_in[62]
  PIN wd_in[63]
    DIRECTION INPUT ;
    USE SIGNAL ;
    SHAPE ABUTMENT ;
    PORT
      LAYER metal3 ;
      RECT 0.000 108.325 0.070 108.395 ;
    END
  END wd_in[63]
  PIN wd_in[64]
    DIRECTION INPUT ;
    USE SIGNAL ;
    SHAPE ABUTMENT ;
    PORT
      LAYER metal3 ;
      RECT 0.000 108.885 0.070 108.955 ;
    END
  END wd_in[64]
  PIN wd_in[65]
    DIRECTION INPUT ;
    USE SIGNAL ;
    SHAPE ABUTMENT ;
    PORT
      LAYER metal3 ;
      RECT 0.000 109.445 0.070 109.515 ;
    END
  END wd_in[65]
  PIN wd_in[66]
    DIRECTION INPUT ;
    USE SIGNAL ;
    SHAPE ABUTMENT ;
    PORT
      LAYER metal3 ;
      RECT 0.000 110.005 0.070 110.075 ;
    END
  END wd_in[66]
  PIN wd_in[67]
    DIRECTION INPUT ;
    USE SIGNAL ;
    SHAPE ABUTMENT ;
    PORT
      LAYER metal3 ;
      RECT 0.000 110.565 0.070 110.635 ;
    END
  END wd_in[67]
  PIN wd_in[68]
    DIRECTION INPUT ;
    USE SIGNAL ;
    SHAPE ABUTMENT ;
    PORT
      LAYER metal3 ;
      RECT 0.000 111.125 0.070 111.195 ;
    END
  END wd_in[68]
  PIN wd_in[69]
    DIRECTION INPUT ;
    USE SIGNAL ;
    SHAPE ABUTMENT ;
    PORT
      LAYER metal3 ;
      RECT 0.000 111.685 0.070 111.755 ;
    END
  END wd_in[69]
  PIN wd_in[70]
    DIRECTION INPUT ;
    USE SIGNAL ;
    SHAPE ABUTMENT ;
    PORT
      LAYER metal3 ;
      RECT 0.000 112.245 0.070 112.315 ;
    END
  END wd_in[70]
  PIN wd_in[71]
    DIRECTION INPUT ;
    USE SIGNAL ;
    SHAPE ABUTMENT ;
    PORT
      LAYER metal3 ;
      RECT 0.000 112.805 0.070 112.875 ;
    END
  END wd_in[71]
  PIN wd_in[72]
    DIRECTION INPUT ;
    USE SIGNAL ;
    SHAPE ABUTMENT ;
    PORT
      LAYER metal3 ;
      RECT 0.000 113.365 0.070 113.435 ;
    END
  END wd_in[72]
  PIN wd_in[73]
    DIRECTION INPUT ;
    USE SIGNAL ;
    SHAPE ABUTMENT ;
    PORT
      LAYER metal3 ;
      RECT 0.000 113.925 0.070 113.995 ;
    END
  END wd_in[73]
  PIN wd_in[74]
    DIRECTION INPUT ;
    USE SIGNAL ;
    SHAPE ABUTMENT ;
    PORT
      LAYER metal3 ;
      RECT 0.000 114.485 0.070 114.555 ;
    END
  END wd_in[74]
  PIN wd_in[75]
    DIRECTION INPUT ;
    USE SIGNAL ;
    SHAPE ABUTMENT ;
    PORT
      LAYER metal3 ;
      RECT 0.000 115.045 0.070 115.115 ;
    END
  END wd_in[75]
  PIN wd_in[76]
    DIRECTION INPUT ;
    USE SIGNAL ;
    SHAPE ABUTMENT ;
    PORT
      LAYER metal3 ;
      RECT 0.000 115.605 0.070 115.675 ;
    END
  END wd_in[76]
  PIN wd_in[77]
    DIRECTION INPUT ;
    USE SIGNAL ;
    SHAPE ABUTMENT ;
    PORT
      LAYER metal3 ;
      RECT 0.000 116.165 0.070 116.235 ;
    END
  END wd_in[77]
  PIN wd_in[78]
    DIRECTION INPUT ;
    USE SIGNAL ;
    SHAPE ABUTMENT ;
    PORT
      LAYER metal3 ;
      RECT 0.000 116.725 0.070 116.795 ;
    END
  END wd_in[78]
  PIN wd_in[79]
    DIRECTION INPUT ;
    USE SIGNAL ;
    SHAPE ABUTMENT ;
    PORT
      LAYER metal3 ;
      RECT 0.000 117.285 0.070 117.355 ;
    END
  END wd_in[79]
  PIN wd_in[80]
    DIRECTION INPUT ;
    USE SIGNAL ;
    SHAPE ABUTMENT ;
    PORT
      LAYER metal3 ;
      RECT 0.000 117.845 0.070 117.915 ;
    END
  END wd_in[80]
  PIN wd_in[81]
    DIRECTION INPUT ;
    USE SIGNAL ;
    SHAPE ABUTMENT ;
    PORT
      LAYER metal3 ;
      RECT 0.000 118.405 0.070 118.475 ;
    END
  END wd_in[81]
  PIN wd_in[82]
    DIRECTION INPUT ;
    USE SIGNAL ;
    SHAPE ABUTMENT ;
    PORT
      LAYER metal3 ;
      RECT 0.000 118.965 0.070 119.035 ;
    END
  END wd_in[82]
  PIN wd_in[83]
    DIRECTION INPUT ;
    USE SIGNAL ;
    SHAPE ABUTMENT ;
    PORT
      LAYER metal3 ;
      RECT 0.000 119.525 0.070 119.595 ;
    END
  END wd_in[83]
  PIN wd_in[84]
    DIRECTION INPUT ;
    USE SIGNAL ;
    SHAPE ABUTMENT ;
    PORT
      LAYER metal3 ;
      RECT 0.000 120.085 0.070 120.155 ;
    END
  END wd_in[84]
  PIN wd_in[85]
    DIRECTION INPUT ;
    USE SIGNAL ;
    SHAPE ABUTMENT ;
    PORT
      LAYER metal3 ;
      RECT 0.000 120.645 0.070 120.715 ;
    END
  END wd_in[85]
  PIN wd_in[86]
    DIRECTION INPUT ;
    USE SIGNAL ;
    SHAPE ABUTMENT ;
    PORT
      LAYER metal3 ;
      RECT 0.000 121.205 0.070 121.275 ;
    END
  END wd_in[86]
  PIN wd_in[87]
    DIRECTION INPUT ;
    USE SIGNAL ;
    SHAPE ABUTMENT ;
    PORT
      LAYER metal3 ;
      RECT 0.000 121.765 0.070 121.835 ;
    END
  END wd_in[87]
  PIN wd_in[88]
    DIRECTION INPUT ;
    USE SIGNAL ;
    SHAPE ABUTMENT ;
    PORT
      LAYER metal3 ;
      RECT 0.000 122.325 0.070 122.395 ;
    END
  END wd_in[88]
  PIN wd_in[89]
    DIRECTION INPUT ;
    USE SIGNAL ;
    SHAPE ABUTMENT ;
    PORT
      LAYER metal3 ;
      RECT 0.000 122.885 0.070 122.955 ;
    END
  END wd_in[89]
  PIN wd_in[90]
    DIRECTION INPUT ;
    USE SIGNAL ;
    SHAPE ABUTMENT ;
    PORT
      LAYER metal3 ;
      RECT 0.000 123.445 0.070 123.515 ;
    END
  END wd_in[90]
  PIN wd_in[91]
    DIRECTION INPUT ;
    USE SIGNAL ;
    SHAPE ABUTMENT ;
    PORT
      LAYER metal3 ;
      RECT 0.000 124.005 0.070 124.075 ;
    END
  END wd_in[91]
  PIN wd_in[92]
    DIRECTION INPUT ;
    USE SIGNAL ;
    SHAPE ABUTMENT ;
    PORT
      LAYER metal3 ;
      RECT 0.000 124.565 0.070 124.635 ;
    END
  END wd_in[92]
  PIN wd_in[93]
    DIRECTION INPUT ;
    USE SIGNAL ;
    SHAPE ABUTMENT ;
    PORT
      LAYER metal3 ;
      RECT 0.000 125.125 0.070 125.195 ;
    END
  END wd_in[93]
  PIN wd_in[94]
    DIRECTION INPUT ;
    USE SIGNAL ;
    SHAPE ABUTMENT ;
    PORT
      LAYER metal3 ;
      RECT 0.000 125.685 0.070 125.755 ;
    END
  END wd_in[94]
  PIN wd_in[95]
    DIRECTION INPUT ;
    USE SIGNAL ;
    SHAPE ABUTMENT ;
    PORT
      LAYER metal3 ;
      RECT 0.000 126.245 0.070 126.315 ;
    END
  END wd_in[95]
  PIN wd_in[96]
    DIRECTION INPUT ;
    USE SIGNAL ;
    SHAPE ABUTMENT ;
    PORT
      LAYER metal3 ;
      RECT 0.000 126.805 0.070 126.875 ;
    END
  END wd_in[96]
  PIN wd_in[97]
    DIRECTION INPUT ;
    USE SIGNAL ;
    SHAPE ABUTMENT ;
    PORT
      LAYER metal3 ;
      RECT 0.000 127.365 0.070 127.435 ;
    END
  END wd_in[97]
  PIN wd_in[98]
    DIRECTION INPUT ;
    USE SIGNAL ;
    SHAPE ABUTMENT ;
    PORT
      LAYER metal3 ;
      RECT 0.000 127.925 0.070 127.995 ;
    END
  END wd_in[98]
  PIN wd_in[99]
    DIRECTION INPUT ;
    USE SIGNAL ;
    SHAPE ABUTMENT ;
    PORT
      LAYER metal3 ;
      RECT 0.000 128.485 0.070 128.555 ;
    END
  END wd_in[99]
  PIN wd_in[100]
    DIRECTION INPUT ;
    USE SIGNAL ;
    SHAPE ABUTMENT ;
    PORT
      LAYER metal3 ;
      RECT 0.000 129.045 0.070 129.115 ;
    END
  END wd_in[100]
  PIN wd_in[101]
    DIRECTION INPUT ;
    USE SIGNAL ;
    SHAPE ABUTMENT ;
    PORT
      LAYER metal3 ;
      RECT 0.000 129.605 0.070 129.675 ;
    END
  END wd_in[101]
  PIN wd_in[102]
    DIRECTION INPUT ;
    USE SIGNAL ;
    SHAPE ABUTMENT ;
    PORT
      LAYER metal3 ;
      RECT 0.000 130.165 0.070 130.235 ;
    END
  END wd_in[102]
  PIN wd_in[103]
    DIRECTION INPUT ;
    USE SIGNAL ;
    SHAPE ABUTMENT ;
    PORT
      LAYER metal3 ;
      RECT 0.000 130.725 0.070 130.795 ;
    END
  END wd_in[103]
  PIN wd_in[104]
    DIRECTION INPUT ;
    USE SIGNAL ;
    SHAPE ABUTMENT ;
    PORT
      LAYER metal3 ;
      RECT 0.000 131.285 0.070 131.355 ;
    END
  END wd_in[104]
  PIN wd_in[105]
    DIRECTION INPUT ;
    USE SIGNAL ;
    SHAPE ABUTMENT ;
    PORT
      LAYER metal3 ;
      RECT 0.000 131.845 0.070 131.915 ;
    END
  END wd_in[105]
  PIN wd_in[106]
    DIRECTION INPUT ;
    USE SIGNAL ;
    SHAPE ABUTMENT ;
    PORT
      LAYER metal3 ;
      RECT 0.000 132.405 0.070 132.475 ;
    END
  END wd_in[106]
  PIN wd_in[107]
    DIRECTION INPUT ;
    USE SIGNAL ;
    SHAPE ABUTMENT ;
    PORT
      LAYER metal3 ;
      RECT 0.000 132.965 0.070 133.035 ;
    END
  END wd_in[107]
  PIN wd_in[108]
    DIRECTION INPUT ;
    USE SIGNAL ;
    SHAPE ABUTMENT ;
    PORT
      LAYER metal3 ;
      RECT 0.000 133.525 0.070 133.595 ;
    END
  END wd_in[108]
  PIN wd_in[109]
    DIRECTION INPUT ;
    USE SIGNAL ;
    SHAPE ABUTMENT ;
    PORT
      LAYER metal3 ;
      RECT 0.000 134.085 0.070 134.155 ;
    END
  END wd_in[109]
  PIN wd_in[110]
    DIRECTION INPUT ;
    USE SIGNAL ;
    SHAPE ABUTMENT ;
    PORT
      LAYER metal3 ;
      RECT 0.000 134.645 0.070 134.715 ;
    END
  END wd_in[110]
  PIN wd_in[111]
    DIRECTION INPUT ;
    USE SIGNAL ;
    SHAPE ABUTMENT ;
    PORT
      LAYER metal3 ;
      RECT 0.000 135.205 0.070 135.275 ;
    END
  END wd_in[111]
  PIN wd_in[112]
    DIRECTION INPUT ;
    USE SIGNAL ;
    SHAPE ABUTMENT ;
    PORT
      LAYER metal3 ;
      RECT 0.000 135.765 0.070 135.835 ;
    END
  END wd_in[112]
  PIN wd_in[113]
    DIRECTION INPUT ;
    USE SIGNAL ;
    SHAPE ABUTMENT ;
    PORT
      LAYER metal3 ;
      RECT 0.000 136.325 0.070 136.395 ;
    END
  END wd_in[113]
  PIN wd_in[114]
    DIRECTION INPUT ;
    USE SIGNAL ;
    SHAPE ABUTMENT ;
    PORT
      LAYER metal3 ;
      RECT 0.000 136.885 0.070 136.955 ;
    END
  END wd_in[114]
  PIN wd_in[115]
    DIRECTION INPUT ;
    USE SIGNAL ;
    SHAPE ABUTMENT ;
    PORT
      LAYER metal3 ;
      RECT 0.000 137.445 0.070 137.515 ;
    END
  END wd_in[115]
  PIN wd_in[116]
    DIRECTION INPUT ;
    USE SIGNAL ;
    SHAPE ABUTMENT ;
    PORT
      LAYER metal3 ;
      RECT 0.000 138.005 0.070 138.075 ;
    END
  END wd_in[116]
  PIN wd_in[117]
    DIRECTION INPUT ;
    USE SIGNAL ;
    SHAPE ABUTMENT ;
    PORT
      LAYER metal3 ;
      RECT 0.000 138.565 0.070 138.635 ;
    END
  END wd_in[117]
  PIN wd_in[118]
    DIRECTION INPUT ;
    USE SIGNAL ;
    SHAPE ABUTMENT ;
    PORT
      LAYER metal3 ;
      RECT 0.000 139.125 0.070 139.195 ;
    END
  END wd_in[118]
  PIN wd_in[119]
    DIRECTION INPUT ;
    USE SIGNAL ;
    SHAPE ABUTMENT ;
    PORT
      LAYER metal3 ;
      RECT 0.000 139.685 0.070 139.755 ;
    END
  END wd_in[119]
  PIN wd_in[120]
    DIRECTION INPUT ;
    USE SIGNAL ;
    SHAPE ABUTMENT ;
    PORT
      LAYER metal3 ;
      RECT 0.000 140.245 0.070 140.315 ;
    END
  END wd_in[120]
  PIN wd_in[121]
    DIRECTION INPUT ;
    USE SIGNAL ;
    SHAPE ABUTMENT ;
    PORT
      LAYER metal3 ;
      RECT 0.000 140.805 0.070 140.875 ;
    END
  END wd_in[121]
  PIN wd_in[122]
    DIRECTION INPUT ;
    USE SIGNAL ;
    SHAPE ABUTMENT ;
    PORT
      LAYER metal3 ;
      RECT 0.000 141.365 0.070 141.435 ;
    END
  END wd_in[122]
  PIN wd_in[123]
    DIRECTION INPUT ;
    USE SIGNAL ;
    SHAPE ABUTMENT ;
    PORT
      LAYER metal3 ;
      RECT 0.000 141.925 0.070 141.995 ;
    END
  END wd_in[123]
  PIN wd_in[124]
    DIRECTION INPUT ;
    USE SIGNAL ;
    SHAPE ABUTMENT ;
    PORT
      LAYER metal3 ;
      RECT 0.000 142.485 0.070 142.555 ;
    END
  END wd_in[124]
  PIN wd_in[125]
    DIRECTION INPUT ;
    USE SIGNAL ;
    SHAPE ABUTMENT ;
    PORT
      LAYER metal3 ;
      RECT 0.000 143.045 0.070 143.115 ;
    END
  END wd_in[125]
  PIN wd_in[126]
    DIRECTION INPUT ;
    USE SIGNAL ;
    SHAPE ABUTMENT ;
    PORT
      LAYER metal3 ;
      RECT 0.000 143.605 0.070 143.675 ;
    END
  END wd_in[126]
  PIN wd_in[127]
    DIRECTION INPUT ;
    USE SIGNAL ;
    SHAPE ABUTMENT ;
    PORT
      LAYER metal3 ;
      RECT 0.000 144.165 0.070 144.235 ;
    END
  END wd_in[127]
  PIN w_addr_in[0]
    DIRECTION INPUT ;
    USE SIGNAL ;
    SHAPE ABUTMENT ;
    PORT
      LAYER metal3 ;
      RECT 0.000 144.725 0.070 144.795 ;
    END
  END w_addr_in[0]
  PIN w_addr_in[1]
    DIRECTION INPUT ;
    USE SIGNAL ;
    SHAPE ABUTMENT ;
    PORT
      LAYER metal3 ;
      RECT 0.000 145.285 0.070 145.355 ;
    END
  END w_addr_in[1]
  PIN w_addr_in[2]
    DIRECTION INPUT ;
    USE SIGNAL ;
    SHAPE ABUTMENT ;
    PORT
      LAYER metal3 ;
      RECT 0.000 145.845 0.070 145.915 ;
    END
  END w_addr_in[2]
  PIN w_addr_in[3]
    DIRECTION INPUT ;
    USE SIGNAL ;
    SHAPE ABUTMENT ;
    PORT
      LAYER metal3 ;
      RECT 0.000 146.405 0.070 146.475 ;
    END
  END w_addr_in[3]
  PIN w_addr_in[4]
    DIRECTION INPUT ;
    USE SIGNAL ;
    SHAPE ABUTMENT ;
    PORT
      LAYER metal3 ;
      RECT 0.000 146.965 0.070 147.035 ;
    END
  END w_addr_in[4]
  PIN w_addr_in[5]
    DIRECTION INPUT ;
    USE SIGNAL ;
    SHAPE ABUTMENT ;
    PORT
      LAYER metal3 ;
      RECT 0.000 147.525 0.070 147.595 ;
    END
  END w_addr_in[5]
  PIN w_addr_in[6]
    DIRECTION INPUT ;
    USE SIGNAL ;
    SHAPE ABUTMENT ;
    PORT
      LAYER metal3 ;
      RECT 0.000 148.085 0.070 148.155 ;
    END
  END w_addr_in[6]
  PIN w_ce_in
    DIRECTION INPUT ;
    USE SIGNAL ;
    SHAPE ABUTMENT ;
    PORT
      LAYER metal3 ;
      RECT 0.000 148.645 0.070 148.715 ;
    END
  END w_ce_in
  PIN rd_out[0]
    DIRECTION OUTPUT ;
    USE SIGNAL ;
    SHAPE ABUTMENT ;
    PORT
      LAYER metal3 ;
      RECT 0.000 156.625 0.070 156.695 ;
    END
  END rd_out[0]
  PIN rd_out[1]
    DIRECTION OUTPUT ;
    USE SIGNAL ;
    SHAPE ABUTMENT ;
    PORT
      LAYER metal3 ;
      RECT 0.000 157.185 0.070 157.255 ;
    END
  END rd_out[1]
  PIN rd_out[2]
    DIRECTION OUTPUT ;
    USE SIGNAL ;
    SHAPE ABUTMENT ;
    PORT
      LAYER metal3 ;
      RECT 0.000 157.745 0.070 157.815 ;
    END
  END rd_out[2]
  PIN rd_out[3]
    DIRECTION OUTPUT ;
    USE SIGNAL ;
    SHAPE ABUTMENT ;
    PORT
      LAYER metal3 ;
      RECT 0.000 158.305 0.070 158.375 ;
    END
  END rd_out[3]
  PIN rd_out[4]
    DIRECTION OUTPUT ;
    USE SIGNAL ;
    SHAPE ABUTMENT ;
    PORT
      LAYER metal3 ;
      RECT 0.000 158.865 0.070 158.935 ;
    END
  END rd_out[4]
  PIN rd_out[5]
    DIRECTION OUTPUT ;
    USE SIGNAL ;
    SHAPE ABUTMENT ;
    PORT
      LAYER metal3 ;
      RECT 0.000 159.425 0.070 159.495 ;
    END
  END rd_out[5]
  PIN rd_out[6]
    DIRECTION OUTPUT ;
    USE SIGNAL ;
    SHAPE ABUTMENT ;
    PORT
      LAYER metal3 ;
      RECT 0.000 159.985 0.070 160.055 ;
    END
  END rd_out[6]
  PIN rd_out[7]
    DIRECTION OUTPUT ;
    USE SIGNAL ;
    SHAPE ABUTMENT ;
    PORT
      LAYER metal3 ;
      RECT 0.000 160.545 0.070 160.615 ;
    END
  END rd_out[7]
  PIN rd_out[8]
    DIRECTION OUTPUT ;
    USE SIGNAL ;
    SHAPE ABUTMENT ;
    PORT
      LAYER metal3 ;
      RECT 0.000 161.105 0.070 161.175 ;
    END
  END rd_out[8]
  PIN rd_out[9]
    DIRECTION OUTPUT ;
    USE SIGNAL ;
    SHAPE ABUTMENT ;
    PORT
      LAYER metal3 ;
      RECT 0.000 161.665 0.070 161.735 ;
    END
  END rd_out[9]
  PIN rd_out[10]
    DIRECTION OUTPUT ;
    USE SIGNAL ;
    SHAPE ABUTMENT ;
    PORT
      LAYER metal3 ;
      RECT 0.000 162.225 0.070 162.295 ;
    END
  END rd_out[10]
  PIN rd_out[11]
    DIRECTION OUTPUT ;
    USE SIGNAL ;
    SHAPE ABUTMENT ;
    PORT
      LAYER metal3 ;
      RECT 0.000 162.785 0.070 162.855 ;
    END
  END rd_out[11]
  PIN rd_out[12]
    DIRECTION OUTPUT ;
    USE SIGNAL ;
    SHAPE ABUTMENT ;
    PORT
      LAYER metal3 ;
      RECT 0.000 163.345 0.070 163.415 ;
    END
  END rd_out[12]
  PIN rd_out[13]
    DIRECTION OUTPUT ;
    USE SIGNAL ;
    SHAPE ABUTMENT ;
    PORT
      LAYER metal3 ;
      RECT 0.000 163.905 0.070 163.975 ;
    END
  END rd_out[13]
  PIN rd_out[14]
    DIRECTION OUTPUT ;
    USE SIGNAL ;
    SHAPE ABUTMENT ;
    PORT
      LAYER metal3 ;
      RECT 0.000 164.465 0.070 164.535 ;
    END
  END rd_out[14]
  PIN rd_out[15]
    DIRECTION OUTPUT ;
    USE SIGNAL ;
    SHAPE ABUTMENT ;
    PORT
      LAYER metal3 ;
      RECT 0.000 165.025 0.070 165.095 ;
    END
  END rd_out[15]
  PIN rd_out[16]
    DIRECTION OUTPUT ;
    USE SIGNAL ;
    SHAPE ABUTMENT ;
    PORT
      LAYER metal3 ;
      RECT 0.000 165.585 0.070 165.655 ;
    END
  END rd_out[16]
  PIN rd_out[17]
    DIRECTION OUTPUT ;
    USE SIGNAL ;
    SHAPE ABUTMENT ;
    PORT
      LAYER metal3 ;
      RECT 0.000 166.145 0.070 166.215 ;
    END
  END rd_out[17]
  PIN rd_out[18]
    DIRECTION OUTPUT ;
    USE SIGNAL ;
    SHAPE ABUTMENT ;
    PORT
      LAYER metal3 ;
      RECT 0.000 166.705 0.070 166.775 ;
    END
  END rd_out[18]
  PIN rd_out[19]
    DIRECTION OUTPUT ;
    USE SIGNAL ;
    SHAPE ABUTMENT ;
    PORT
      LAYER metal3 ;
      RECT 0.000 167.265 0.070 167.335 ;
    END
  END rd_out[19]
  PIN rd_out[20]
    DIRECTION OUTPUT ;
    USE SIGNAL ;
    SHAPE ABUTMENT ;
    PORT
      LAYER metal3 ;
      RECT 0.000 167.825 0.070 167.895 ;
    END
  END rd_out[20]
  PIN rd_out[21]
    DIRECTION OUTPUT ;
    USE SIGNAL ;
    SHAPE ABUTMENT ;
    PORT
      LAYER metal3 ;
      RECT 0.000 168.385 0.070 168.455 ;
    END
  END rd_out[21]
  PIN rd_out[22]
    DIRECTION OUTPUT ;
    USE SIGNAL ;
    SHAPE ABUTMENT ;
    PORT
      LAYER metal3 ;
      RECT 0.000 168.945 0.070 169.015 ;
    END
  END rd_out[22]
  PIN rd_out[23]
    DIRECTION OUTPUT ;
    USE SIGNAL ;
    SHAPE ABUTMENT ;
    PORT
      LAYER metal3 ;
      RECT 0.000 169.505 0.070 169.575 ;
    END
  END rd_out[23]
  PIN rd_out[24]
    DIRECTION OUTPUT ;
    USE SIGNAL ;
    SHAPE ABUTMENT ;
    PORT
      LAYER metal3 ;
      RECT 0.000 170.065 0.070 170.135 ;
    END
  END rd_out[24]
  PIN rd_out[25]
    DIRECTION OUTPUT ;
    USE SIGNAL ;
    SHAPE ABUTMENT ;
    PORT
      LAYER metal3 ;
      RECT 0.000 170.625 0.070 170.695 ;
    END
  END rd_out[25]
  PIN rd_out[26]
    DIRECTION OUTPUT ;
    USE SIGNAL ;
    SHAPE ABUTMENT ;
    PORT
      LAYER metal3 ;
      RECT 0.000 171.185 0.070 171.255 ;
    END
  END rd_out[26]
  PIN rd_out[27]
    DIRECTION OUTPUT ;
    USE SIGNAL ;
    SHAPE ABUTMENT ;
    PORT
      LAYER metal3 ;
      RECT 0.000 171.745 0.070 171.815 ;
    END
  END rd_out[27]
  PIN rd_out[28]
    DIRECTION OUTPUT ;
    USE SIGNAL ;
    SHAPE ABUTMENT ;
    PORT
      LAYER metal3 ;
      RECT 0.000 172.305 0.070 172.375 ;
    END
  END rd_out[28]
  PIN rd_out[29]
    DIRECTION OUTPUT ;
    USE SIGNAL ;
    SHAPE ABUTMENT ;
    PORT
      LAYER metal3 ;
      RECT 0.000 172.865 0.070 172.935 ;
    END
  END rd_out[29]
  PIN rd_out[30]
    DIRECTION OUTPUT ;
    USE SIGNAL ;
    SHAPE ABUTMENT ;
    PORT
      LAYER metal3 ;
      RECT 0.000 173.425 0.070 173.495 ;
    END
  END rd_out[30]
  PIN rd_out[31]
    DIRECTION OUTPUT ;
    USE SIGNAL ;
    SHAPE ABUTMENT ;
    PORT
      LAYER metal3 ;
      RECT 0.000 173.985 0.070 174.055 ;
    END
  END rd_out[31]
  PIN rd_out[32]
    DIRECTION OUTPUT ;
    USE SIGNAL ;
    SHAPE ABUTMENT ;
    PORT
      LAYER metal3 ;
      RECT 0.000 174.545 0.070 174.615 ;
    END
  END rd_out[32]
  PIN rd_out[33]
    DIRECTION OUTPUT ;
    USE SIGNAL ;
    SHAPE ABUTMENT ;
    PORT
      LAYER metal3 ;
      RECT 0.000 175.105 0.070 175.175 ;
    END
  END rd_out[33]
  PIN rd_out[34]
    DIRECTION OUTPUT ;
    USE SIGNAL ;
    SHAPE ABUTMENT ;
    PORT
      LAYER metal3 ;
      RECT 0.000 175.665 0.070 175.735 ;
    END
  END rd_out[34]
  PIN rd_out[35]
    DIRECTION OUTPUT ;
    USE SIGNAL ;
    SHAPE ABUTMENT ;
    PORT
      LAYER metal3 ;
      RECT 0.000 176.225 0.070 176.295 ;
    END
  END rd_out[35]
  PIN rd_out[36]
    DIRECTION OUTPUT ;
    USE SIGNAL ;
    SHAPE ABUTMENT ;
    PORT
      LAYER metal3 ;
      RECT 0.000 176.785 0.070 176.855 ;
    END
  END rd_out[36]
  PIN rd_out[37]
    DIRECTION OUTPUT ;
    USE SIGNAL ;
    SHAPE ABUTMENT ;
    PORT
      LAYER metal3 ;
      RECT 0.000 177.345 0.070 177.415 ;
    END
  END rd_out[37]
  PIN rd_out[38]
    DIRECTION OUTPUT ;
    USE SIGNAL ;
    SHAPE ABUTMENT ;
    PORT
      LAYER metal3 ;
      RECT 0.000 177.905 0.070 177.975 ;
    END
  END rd_out[38]
  PIN rd_out[39]
    DIRECTION OUTPUT ;
    USE SIGNAL ;
    SHAPE ABUTMENT ;
    PORT
      LAYER metal3 ;
      RECT 0.000 178.465 0.070 178.535 ;
    END
  END rd_out[39]
  PIN rd_out[40]
    DIRECTION OUTPUT ;
    USE SIGNAL ;
    SHAPE ABUTMENT ;
    PORT
      LAYER metal3 ;
      RECT 0.000 179.025 0.070 179.095 ;
    END
  END rd_out[40]
  PIN rd_out[41]
    DIRECTION OUTPUT ;
    USE SIGNAL ;
    SHAPE ABUTMENT ;
    PORT
      LAYER metal3 ;
      RECT 0.000 179.585 0.070 179.655 ;
    END
  END rd_out[41]
  PIN rd_out[42]
    DIRECTION OUTPUT ;
    USE SIGNAL ;
    SHAPE ABUTMENT ;
    PORT
      LAYER metal3 ;
      RECT 0.000 180.145 0.070 180.215 ;
    END
  END rd_out[42]
  PIN rd_out[43]
    DIRECTION OUTPUT ;
    USE SIGNAL ;
    SHAPE ABUTMENT ;
    PORT
      LAYER metal3 ;
      RECT 0.000 180.705 0.070 180.775 ;
    END
  END rd_out[43]
  PIN rd_out[44]
    DIRECTION OUTPUT ;
    USE SIGNAL ;
    SHAPE ABUTMENT ;
    PORT
      LAYER metal3 ;
      RECT 0.000 181.265 0.070 181.335 ;
    END
  END rd_out[44]
  PIN rd_out[45]
    DIRECTION OUTPUT ;
    USE SIGNAL ;
    SHAPE ABUTMENT ;
    PORT
      LAYER metal3 ;
      RECT 0.000 181.825 0.070 181.895 ;
    END
  END rd_out[45]
  PIN rd_out[46]
    DIRECTION OUTPUT ;
    USE SIGNAL ;
    SHAPE ABUTMENT ;
    PORT
      LAYER metal3 ;
      RECT 0.000 182.385 0.070 182.455 ;
    END
  END rd_out[46]
  PIN rd_out[47]
    DIRECTION OUTPUT ;
    USE SIGNAL ;
    SHAPE ABUTMENT ;
    PORT
      LAYER metal3 ;
      RECT 0.000 182.945 0.070 183.015 ;
    END
  END rd_out[47]
  PIN rd_out[48]
    DIRECTION OUTPUT ;
    USE SIGNAL ;
    SHAPE ABUTMENT ;
    PORT
      LAYER metal3 ;
      RECT 0.000 183.505 0.070 183.575 ;
    END
  END rd_out[48]
  PIN rd_out[49]
    DIRECTION OUTPUT ;
    USE SIGNAL ;
    SHAPE ABUTMENT ;
    PORT
      LAYER metal3 ;
      RECT 0.000 184.065 0.070 184.135 ;
    END
  END rd_out[49]
  PIN rd_out[50]
    DIRECTION OUTPUT ;
    USE SIGNAL ;
    SHAPE ABUTMENT ;
    PORT
      LAYER metal3 ;
      RECT 0.000 184.625 0.070 184.695 ;
    END
  END rd_out[50]
  PIN rd_out[51]
    DIRECTION OUTPUT ;
    USE SIGNAL ;
    SHAPE ABUTMENT ;
    PORT
      LAYER metal3 ;
      RECT 0.000 185.185 0.070 185.255 ;
    END
  END rd_out[51]
  PIN rd_out[52]
    DIRECTION OUTPUT ;
    USE SIGNAL ;
    SHAPE ABUTMENT ;
    PORT
      LAYER metal3 ;
      RECT 0.000 185.745 0.070 185.815 ;
    END
  END rd_out[52]
  PIN rd_out[53]
    DIRECTION OUTPUT ;
    USE SIGNAL ;
    SHAPE ABUTMENT ;
    PORT
      LAYER metal3 ;
      RECT 0.000 186.305 0.070 186.375 ;
    END
  END rd_out[53]
  PIN rd_out[54]
    DIRECTION OUTPUT ;
    USE SIGNAL ;
    SHAPE ABUTMENT ;
    PORT
      LAYER metal3 ;
      RECT 0.000 186.865 0.070 186.935 ;
    END
  END rd_out[54]
  PIN rd_out[55]
    DIRECTION OUTPUT ;
    USE SIGNAL ;
    SHAPE ABUTMENT ;
    PORT
      LAYER metal3 ;
      RECT 0.000 187.425 0.070 187.495 ;
    END
  END rd_out[55]
  PIN rd_out[56]
    DIRECTION OUTPUT ;
    USE SIGNAL ;
    SHAPE ABUTMENT ;
    PORT
      LAYER metal3 ;
      RECT 0.000 187.985 0.070 188.055 ;
    END
  END rd_out[56]
  PIN rd_out[57]
    DIRECTION OUTPUT ;
    USE SIGNAL ;
    SHAPE ABUTMENT ;
    PORT
      LAYER metal3 ;
      RECT 0.000 188.545 0.070 188.615 ;
    END
  END rd_out[57]
  PIN rd_out[58]
    DIRECTION OUTPUT ;
    USE SIGNAL ;
    SHAPE ABUTMENT ;
    PORT
      LAYER metal3 ;
      RECT 0.000 189.105 0.070 189.175 ;
    END
  END rd_out[58]
  PIN rd_out[59]
    DIRECTION OUTPUT ;
    USE SIGNAL ;
    SHAPE ABUTMENT ;
    PORT
      LAYER metal3 ;
      RECT 0.000 189.665 0.070 189.735 ;
    END
  END rd_out[59]
  PIN rd_out[60]
    DIRECTION OUTPUT ;
    USE SIGNAL ;
    SHAPE ABUTMENT ;
    PORT
      LAYER metal3 ;
      RECT 0.000 190.225 0.070 190.295 ;
    END
  END rd_out[60]
  PIN rd_out[61]
    DIRECTION OUTPUT ;
    USE SIGNAL ;
    SHAPE ABUTMENT ;
    PORT
      LAYER metal3 ;
      RECT 0.000 190.785 0.070 190.855 ;
    END
  END rd_out[61]
  PIN rd_out[62]
    DIRECTION OUTPUT ;
    USE SIGNAL ;
    SHAPE ABUTMENT ;
    PORT
      LAYER metal3 ;
      RECT 0.000 191.345 0.070 191.415 ;
    END
  END rd_out[62]
  PIN rd_out[63]
    DIRECTION OUTPUT ;
    USE SIGNAL ;
    SHAPE ABUTMENT ;
    PORT
      LAYER metal3 ;
      RECT 0.000 191.905 0.070 191.975 ;
    END
  END rd_out[63]
  PIN rd_out[64]
    DIRECTION OUTPUT ;
    USE SIGNAL ;
    SHAPE ABUTMENT ;
    PORT
      LAYER metal3 ;
      RECT 0.000 192.465 0.070 192.535 ;
    END
  END rd_out[64]
  PIN rd_out[65]
    DIRECTION OUTPUT ;
    USE SIGNAL ;
    SHAPE ABUTMENT ;
    PORT
      LAYER metal3 ;
      RECT 0.000 193.025 0.070 193.095 ;
    END
  END rd_out[65]
  PIN rd_out[66]
    DIRECTION OUTPUT ;
    USE SIGNAL ;
    SHAPE ABUTMENT ;
    PORT
      LAYER metal3 ;
      RECT 0.000 193.585 0.070 193.655 ;
    END
  END rd_out[66]
  PIN rd_out[67]
    DIRECTION OUTPUT ;
    USE SIGNAL ;
    SHAPE ABUTMENT ;
    PORT
      LAYER metal3 ;
      RECT 0.000 194.145 0.070 194.215 ;
    END
  END rd_out[67]
  PIN rd_out[68]
    DIRECTION OUTPUT ;
    USE SIGNAL ;
    SHAPE ABUTMENT ;
    PORT
      LAYER metal3 ;
      RECT 0.000 194.705 0.070 194.775 ;
    END
  END rd_out[68]
  PIN rd_out[69]
    DIRECTION OUTPUT ;
    USE SIGNAL ;
    SHAPE ABUTMENT ;
    PORT
      LAYER metal3 ;
      RECT 0.000 195.265 0.070 195.335 ;
    END
  END rd_out[69]
  PIN rd_out[70]
    DIRECTION OUTPUT ;
    USE SIGNAL ;
    SHAPE ABUTMENT ;
    PORT
      LAYER metal3 ;
      RECT 0.000 195.825 0.070 195.895 ;
    END
  END rd_out[70]
  PIN rd_out[71]
    DIRECTION OUTPUT ;
    USE SIGNAL ;
    SHAPE ABUTMENT ;
    PORT
      LAYER metal3 ;
      RECT 0.000 196.385 0.070 196.455 ;
    END
  END rd_out[71]
  PIN rd_out[72]
    DIRECTION OUTPUT ;
    USE SIGNAL ;
    SHAPE ABUTMENT ;
    PORT
      LAYER metal3 ;
      RECT 0.000 196.945 0.070 197.015 ;
    END
  END rd_out[72]
  PIN rd_out[73]
    DIRECTION OUTPUT ;
    USE SIGNAL ;
    SHAPE ABUTMENT ;
    PORT
      LAYER metal3 ;
      RECT 0.000 197.505 0.070 197.575 ;
    END
  END rd_out[73]
  PIN rd_out[74]
    DIRECTION OUTPUT ;
    USE SIGNAL ;
    SHAPE ABUTMENT ;
    PORT
      LAYER metal3 ;
      RECT 0.000 198.065 0.070 198.135 ;
    END
  END rd_out[74]
  PIN rd_out[75]
    DIRECTION OUTPUT ;
    USE SIGNAL ;
    SHAPE ABUTMENT ;
    PORT
      LAYER metal3 ;
      RECT 0.000 198.625 0.070 198.695 ;
    END
  END rd_out[75]
  PIN rd_out[76]
    DIRECTION OUTPUT ;
    USE SIGNAL ;
    SHAPE ABUTMENT ;
    PORT
      LAYER metal3 ;
      RECT 0.000 199.185 0.070 199.255 ;
    END
  END rd_out[76]
  PIN rd_out[77]
    DIRECTION OUTPUT ;
    USE SIGNAL ;
    SHAPE ABUTMENT ;
    PORT
      LAYER metal3 ;
      RECT 0.000 199.745 0.070 199.815 ;
    END
  END rd_out[77]
  PIN rd_out[78]
    DIRECTION OUTPUT ;
    USE SIGNAL ;
    SHAPE ABUTMENT ;
    PORT
      LAYER metal3 ;
      RECT 0.000 200.305 0.070 200.375 ;
    END
  END rd_out[78]
  PIN rd_out[79]
    DIRECTION OUTPUT ;
    USE SIGNAL ;
    SHAPE ABUTMENT ;
    PORT
      LAYER metal3 ;
      RECT 0.000 200.865 0.070 200.935 ;
    END
  END rd_out[79]
  PIN rd_out[80]
    DIRECTION OUTPUT ;
    USE SIGNAL ;
    SHAPE ABUTMENT ;
    PORT
      LAYER metal3 ;
      RECT 0.000 201.425 0.070 201.495 ;
    END
  END rd_out[80]
  PIN rd_out[81]
    DIRECTION OUTPUT ;
    USE SIGNAL ;
    SHAPE ABUTMENT ;
    PORT
      LAYER metal3 ;
      RECT 0.000 201.985 0.070 202.055 ;
    END
  END rd_out[81]
  PIN rd_out[82]
    DIRECTION OUTPUT ;
    USE SIGNAL ;
    SHAPE ABUTMENT ;
    PORT
      LAYER metal3 ;
      RECT 0.000 202.545 0.070 202.615 ;
    END
  END rd_out[82]
  PIN rd_out[83]
    DIRECTION OUTPUT ;
    USE SIGNAL ;
    SHAPE ABUTMENT ;
    PORT
      LAYER metal3 ;
      RECT 0.000 203.105 0.070 203.175 ;
    END
  END rd_out[83]
  PIN rd_out[84]
    DIRECTION OUTPUT ;
    USE SIGNAL ;
    SHAPE ABUTMENT ;
    PORT
      LAYER metal3 ;
      RECT 0.000 203.665 0.070 203.735 ;
    END
  END rd_out[84]
  PIN rd_out[85]
    DIRECTION OUTPUT ;
    USE SIGNAL ;
    SHAPE ABUTMENT ;
    PORT
      LAYER metal3 ;
      RECT 0.000 204.225 0.070 204.295 ;
    END
  END rd_out[85]
  PIN rd_out[86]
    DIRECTION OUTPUT ;
    USE SIGNAL ;
    SHAPE ABUTMENT ;
    PORT
      LAYER metal3 ;
      RECT 0.000 204.785 0.070 204.855 ;
    END
  END rd_out[86]
  PIN rd_out[87]
    DIRECTION OUTPUT ;
    USE SIGNAL ;
    SHAPE ABUTMENT ;
    PORT
      LAYER metal3 ;
      RECT 0.000 205.345 0.070 205.415 ;
    END
  END rd_out[87]
  PIN rd_out[88]
    DIRECTION OUTPUT ;
    USE SIGNAL ;
    SHAPE ABUTMENT ;
    PORT
      LAYER metal3 ;
      RECT 0.000 205.905 0.070 205.975 ;
    END
  END rd_out[88]
  PIN rd_out[89]
    DIRECTION OUTPUT ;
    USE SIGNAL ;
    SHAPE ABUTMENT ;
    PORT
      LAYER metal3 ;
      RECT 0.000 206.465 0.070 206.535 ;
    END
  END rd_out[89]
  PIN rd_out[90]
    DIRECTION OUTPUT ;
    USE SIGNAL ;
    SHAPE ABUTMENT ;
    PORT
      LAYER metal3 ;
      RECT 0.000 207.025 0.070 207.095 ;
    END
  END rd_out[90]
  PIN rd_out[91]
    DIRECTION OUTPUT ;
    USE SIGNAL ;
    SHAPE ABUTMENT ;
    PORT
      LAYER metal3 ;
      RECT 0.000 207.585 0.070 207.655 ;
    END
  END rd_out[91]
  PIN rd_out[92]
    DIRECTION OUTPUT ;
    USE SIGNAL ;
    SHAPE ABUTMENT ;
    PORT
      LAYER metal3 ;
      RECT 0.000 208.145 0.070 208.215 ;
    END
  END rd_out[92]
  PIN rd_out[93]
    DIRECTION OUTPUT ;
    USE SIGNAL ;
    SHAPE ABUTMENT ;
    PORT
      LAYER metal3 ;
      RECT 0.000 208.705 0.070 208.775 ;
    END
  END rd_out[93]
  PIN rd_out[94]
    DIRECTION OUTPUT ;
    USE SIGNAL ;
    SHAPE ABUTMENT ;
    PORT
      LAYER metal3 ;
      RECT 0.000 209.265 0.070 209.335 ;
    END
  END rd_out[94]
  PIN rd_out[95]
    DIRECTION OUTPUT ;
    USE SIGNAL ;
    SHAPE ABUTMENT ;
    PORT
      LAYER metal3 ;
      RECT 0.000 209.825 0.070 209.895 ;
    END
  END rd_out[95]
  PIN rd_out[96]
    DIRECTION OUTPUT ;
    USE SIGNAL ;
    SHAPE ABUTMENT ;
    PORT
      LAYER metal3 ;
      RECT 0.000 210.385 0.070 210.455 ;
    END
  END rd_out[96]
  PIN rd_out[97]
    DIRECTION OUTPUT ;
    USE SIGNAL ;
    SHAPE ABUTMENT ;
    PORT
      LAYER metal3 ;
      RECT 0.000 210.945 0.070 211.015 ;
    END
  END rd_out[97]
  PIN rd_out[98]
    DIRECTION OUTPUT ;
    USE SIGNAL ;
    SHAPE ABUTMENT ;
    PORT
      LAYER metal3 ;
      RECT 0.000 211.505 0.070 211.575 ;
    END
  END rd_out[98]
  PIN rd_out[99]
    DIRECTION OUTPUT ;
    USE SIGNAL ;
    SHAPE ABUTMENT ;
    PORT
      LAYER metal3 ;
      RECT 0.000 212.065 0.070 212.135 ;
    END
  END rd_out[99]
  PIN rd_out[100]
    DIRECTION OUTPUT ;
    USE SIGNAL ;
    SHAPE ABUTMENT ;
    PORT
      LAYER metal3 ;
      RECT 0.000 212.625 0.070 212.695 ;
    END
  END rd_out[100]
  PIN rd_out[101]
    DIRECTION OUTPUT ;
    USE SIGNAL ;
    SHAPE ABUTMENT ;
    PORT
      LAYER metal3 ;
      RECT 0.000 213.185 0.070 213.255 ;
    END
  END rd_out[101]
  PIN rd_out[102]
    DIRECTION OUTPUT ;
    USE SIGNAL ;
    SHAPE ABUTMENT ;
    PORT
      LAYER metal3 ;
      RECT 0.000 213.745 0.070 213.815 ;
    END
  END rd_out[102]
  PIN rd_out[103]
    DIRECTION OUTPUT ;
    USE SIGNAL ;
    SHAPE ABUTMENT ;
    PORT
      LAYER metal3 ;
      RECT 0.000 214.305 0.070 214.375 ;
    END
  END rd_out[103]
  PIN rd_out[104]
    DIRECTION OUTPUT ;
    USE SIGNAL ;
    SHAPE ABUTMENT ;
    PORT
      LAYER metal3 ;
      RECT 0.000 214.865 0.070 214.935 ;
    END
  END rd_out[104]
  PIN rd_out[105]
    DIRECTION OUTPUT ;
    USE SIGNAL ;
    SHAPE ABUTMENT ;
    PORT
      LAYER metal3 ;
      RECT 0.000 215.425 0.070 215.495 ;
    END
  END rd_out[105]
  PIN rd_out[106]
    DIRECTION OUTPUT ;
    USE SIGNAL ;
    SHAPE ABUTMENT ;
    PORT
      LAYER metal3 ;
      RECT 0.000 215.985 0.070 216.055 ;
    END
  END rd_out[106]
  PIN rd_out[107]
    DIRECTION OUTPUT ;
    USE SIGNAL ;
    SHAPE ABUTMENT ;
    PORT
      LAYER metal3 ;
      RECT 0.000 216.545 0.070 216.615 ;
    END
  END rd_out[107]
  PIN rd_out[108]
    DIRECTION OUTPUT ;
    USE SIGNAL ;
    SHAPE ABUTMENT ;
    PORT
      LAYER metal3 ;
      RECT 0.000 217.105 0.070 217.175 ;
    END
  END rd_out[108]
  PIN rd_out[109]
    DIRECTION OUTPUT ;
    USE SIGNAL ;
    SHAPE ABUTMENT ;
    PORT
      LAYER metal3 ;
      RECT 0.000 217.665 0.070 217.735 ;
    END
  END rd_out[109]
  PIN rd_out[110]
    DIRECTION OUTPUT ;
    USE SIGNAL ;
    SHAPE ABUTMENT ;
    PORT
      LAYER metal3 ;
      RECT 0.000 218.225 0.070 218.295 ;
    END
  END rd_out[110]
  PIN rd_out[111]
    DIRECTION OUTPUT ;
    USE SIGNAL ;
    SHAPE ABUTMENT ;
    PORT
      LAYER metal3 ;
      RECT 0.000 218.785 0.070 218.855 ;
    END
  END rd_out[111]
  PIN rd_out[112]
    DIRECTION OUTPUT ;
    USE SIGNAL ;
    SHAPE ABUTMENT ;
    PORT
      LAYER metal3 ;
      RECT 0.000 219.345 0.070 219.415 ;
    END
  END rd_out[112]
  PIN rd_out[113]
    DIRECTION OUTPUT ;
    USE SIGNAL ;
    SHAPE ABUTMENT ;
    PORT
      LAYER metal3 ;
      RECT 0.000 219.905 0.070 219.975 ;
    END
  END rd_out[113]
  PIN rd_out[114]
    DIRECTION OUTPUT ;
    USE SIGNAL ;
    SHAPE ABUTMENT ;
    PORT
      LAYER metal3 ;
      RECT 0.000 220.465 0.070 220.535 ;
    END
  END rd_out[114]
  PIN rd_out[115]
    DIRECTION OUTPUT ;
    USE SIGNAL ;
    SHAPE ABUTMENT ;
    PORT
      LAYER metal3 ;
      RECT 0.000 221.025 0.070 221.095 ;
    END
  END rd_out[115]
  PIN rd_out[116]
    DIRECTION OUTPUT ;
    USE SIGNAL ;
    SHAPE ABUTMENT ;
    PORT
      LAYER metal3 ;
      RECT 0.000 221.585 0.070 221.655 ;
    END
  END rd_out[116]
  PIN rd_out[117]
    DIRECTION OUTPUT ;
    USE SIGNAL ;
    SHAPE ABUTMENT ;
    PORT
      LAYER metal3 ;
      RECT 0.000 222.145 0.070 222.215 ;
    END
  END rd_out[117]
  PIN rd_out[118]
    DIRECTION OUTPUT ;
    USE SIGNAL ;
    SHAPE ABUTMENT ;
    PORT
      LAYER metal3 ;
      RECT 0.000 222.705 0.070 222.775 ;
    END
  END rd_out[118]
  PIN rd_out[119]
    DIRECTION OUTPUT ;
    USE SIGNAL ;
    SHAPE ABUTMENT ;
    PORT
      LAYER metal3 ;
      RECT 0.000 223.265 0.070 223.335 ;
    END
  END rd_out[119]
  PIN rd_out[120]
    DIRECTION OUTPUT ;
    USE SIGNAL ;
    SHAPE ABUTMENT ;
    PORT
      LAYER metal3 ;
      RECT 0.000 223.825 0.070 223.895 ;
    END
  END rd_out[120]
  PIN rd_out[121]
    DIRECTION OUTPUT ;
    USE SIGNAL ;
    SHAPE ABUTMENT ;
    PORT
      LAYER metal3 ;
      RECT 0.000 224.385 0.070 224.455 ;
    END
  END rd_out[121]
  PIN rd_out[122]
    DIRECTION OUTPUT ;
    USE SIGNAL ;
    SHAPE ABUTMENT ;
    PORT
      LAYER metal3 ;
      RECT 0.000 224.945 0.070 225.015 ;
    END
  END rd_out[122]
  PIN rd_out[123]
    DIRECTION OUTPUT ;
    USE SIGNAL ;
    SHAPE ABUTMENT ;
    PORT
      LAYER metal3 ;
      RECT 0.000 225.505 0.070 225.575 ;
    END
  END rd_out[123]
  PIN rd_out[124]
    DIRECTION OUTPUT ;
    USE SIGNAL ;
    SHAPE ABUTMENT ;
    PORT
      LAYER metal3 ;
      RECT 0.000 226.065 0.070 226.135 ;
    END
  END rd_out[124]
  PIN rd_out[125]
    DIRECTION OUTPUT ;
    USE SIGNAL ;
    SHAPE ABUTMENT ;
    PORT
      LAYER metal3 ;
      RECT 0.000 226.625 0.070 226.695 ;
    END
  END rd_out[125]
  PIN rd_out[126]
    DIRECTION OUTPUT ;
    USE SIGNAL ;
    SHAPE ABUTMENT ;
    PORT
      LAYER metal3 ;
      RECT 0.000 227.185 0.070 227.255 ;
    END
  END rd_out[126]
  PIN rd_out[127]
    DIRECTION OUTPUT ;
    USE SIGNAL ;
    SHAPE ABUTMENT ;
    PORT
      LAYER metal3 ;
      RECT 0.000 227.745 0.070 227.815 ;
    END
  END rd_out[127]
  PIN r_addr_in[0]
    DIRECTION INPUT ;
    USE SIGNAL ;
    SHAPE ABUTMENT ;
    PORT
      LAYER metal3 ;
      RECT 0.000 228.305 0.070 228.375 ;
    END
  END r_addr_in[0]
  PIN r_addr_in[1]
    DIRECTION INPUT ;
    USE SIGNAL ;
    SHAPE ABUTMENT ;
    PORT
      LAYER metal3 ;
      RECT 0.000 228.865 0.070 228.935 ;
    END
  END r_addr_in[1]
  PIN r_addr_in[2]
    DIRECTION INPUT ;
    USE SIGNAL ;
    SHAPE ABUTMENT ;
    PORT
      LAYER metal3 ;
      RECT 0.000 229.425 0.070 229.495 ;
    END
  END r_addr_in[2]
  PIN r_addr_in[3]
    DIRECTION INPUT ;
    USE SIGNAL ;
    SHAPE ABUTMENT ;
    PORT
      LAYER metal3 ;
      RECT 0.000 229.985 0.070 230.055 ;
    END
  END r_addr_in[3]
  PIN r_addr_in[4]
    DIRECTION INPUT ;
    USE SIGNAL ;
    SHAPE ABUTMENT ;
    PORT
      LAYER metal3 ;
      RECT 0.000 230.545 0.070 230.615 ;
    END
  END r_addr_in[4]
  PIN r_addr_in[5]
    DIRECTION INPUT ;
    USE SIGNAL ;
    SHAPE ABUTMENT ;
    PORT
      LAYER metal3 ;
      RECT 0.000 231.105 0.070 231.175 ;
    END
  END r_addr_in[5]
  PIN r_addr_in[6]
    DIRECTION INPUT ;
    USE SIGNAL ;
    SHAPE ABUTMENT ;
    PORT
      LAYER metal3 ;
      RECT 0.000 231.665 0.070 231.735 ;
    END
  END r_addr_in[6]
  PIN r_ce_in
    DIRECTION INPUT ;
    USE SIGNAL ;
    SHAPE ABUTMENT ;
    PORT
      LAYER metal3 ;
      RECT 0.000 232.225 0.070 232.295 ;
    END
  END r_ce_in
  PIN clk
    DIRECTION INPUT ;
    USE SIGNAL ;
    SHAPE ABUTMENT ;
    PORT
      LAYER metal3 ;
      RECT 0.000 240.205 0.070 240.275 ;
    END
  END clk
  PIN VSS
    DIRECTION INOUT ;
    USE GROUND ;
    PORT
      LAYER metal4 ;
      RECT 1.260 1.400 1.540 250.600 ;
      RECT 3.500 1.400 3.780 250.600 ;
      RECT 5.740 1.400 6.020 250.600 ;
      RECT 7.980 1.400 8.260 250.600 ;
      RECT 10.220 1.400 10.500 250.600 ;
      RECT 12.460 1.400 12.740 250.600 ;
      RECT 14.700 1.400 14.980 250.600 ;
      RECT 16.940 1.400 17.220 250.600 ;
      RECT 19.180 1.400 19.460 250.600 ;
      RECT 21.420 1.400 21.700 250.600 ;
      RECT 23.660 1.400 23.940 250.600 ;
      RECT 25.900 1.400 26.180 250.600 ;
      RECT 28.140 1.400 28.420 250.600 ;
      RECT 30.380 1.400 30.660 250.600 ;
      RECT 32.620 1.400 32.900 250.600 ;
      RECT 34.860 1.400 35.140 250.600 ;
      RECT 37.100 1.400 37.380 250.600 ;
      RECT 39.340 1.400 39.620 250.600 ;
      RECT 41.580 1.400 41.860 250.600 ;
      RECT 43.820 1.400 44.100 250.600 ;
      RECT 46.060 1.400 46.340 250.600 ;
      RECT 48.300 1.400 48.580 250.600 ;
      RECT 50.540 1.400 50.820 250.600 ;
      RECT 52.780 1.400 53.060 250.600 ;
      RECT 55.020 1.400 55.300 250.600 ;
      RECT 57.260 1.400 57.540 250.600 ;
      RECT 59.500 1.400 59.780 250.600 ;
      RECT 61.740 1.400 62.020 250.600 ;
      RECT 63.980 1.400 64.260 250.600 ;
      RECT 66.220 1.400 66.500 250.600 ;
      RECT 68.460 1.400 68.740 250.600 ;
      RECT 70.700 1.400 70.980 250.600 ;
      RECT 72.940 1.400 73.220 250.600 ;
      RECT 75.180 1.400 75.460 250.600 ;
      RECT 77.420 1.400 77.700 250.600 ;
      RECT 79.660 1.400 79.940 250.600 ;
      RECT 81.900 1.400 82.180 250.600 ;
      RECT 84.140 1.400 84.420 250.600 ;
      RECT 86.380 1.400 86.660 250.600 ;
      RECT 88.620 1.400 88.900 250.600 ;
      RECT 90.860 1.400 91.140 250.600 ;
      RECT 93.100 1.400 93.380 250.600 ;
      RECT 95.340 1.400 95.620 250.600 ;
      RECT 97.580 1.400 97.860 250.600 ;
      RECT 99.820 1.400 100.100 250.600 ;
      RECT 102.060 1.400 102.340 250.600 ;
      RECT 104.300 1.400 104.580 250.600 ;
      RECT 106.540 1.400 106.820 250.600 ;
      RECT 108.780 1.400 109.060 250.600 ;
      RECT 111.020 1.400 111.300 250.600 ;
      RECT 113.260 1.400 113.540 250.600 ;
      RECT 115.500 1.400 115.780 250.600 ;
      RECT 117.740 1.400 118.020 250.600 ;
      RECT 119.980 1.400 120.260 250.600 ;
      RECT 122.220 1.400 122.500 250.600 ;
      RECT 124.460 1.400 124.740 250.600 ;
      RECT 126.700 1.400 126.980 250.600 ;
      RECT 128.940 1.400 129.220 250.600 ;
      RECT 131.180 1.400 131.460 250.600 ;
      RECT 133.420 1.400 133.700 250.600 ;
      RECT 135.660 1.400 135.940 250.600 ;
      RECT 137.900 1.400 138.180 250.600 ;
      RECT 140.140 1.400 140.420 250.600 ;
      RECT 142.380 1.400 142.660 250.600 ;
      RECT 144.620 1.400 144.900 250.600 ;
      RECT 146.860 1.400 147.140 250.600 ;
      RECT 149.100 1.400 149.380 250.600 ;
      RECT 151.340 1.400 151.620 250.600 ;
      RECT 153.580 1.400 153.860 250.600 ;
      RECT 155.820 1.400 156.100 250.600 ;
      RECT 158.060 1.400 158.340 250.600 ;
      RECT 160.300 1.400 160.580 250.600 ;
      RECT 162.540 1.400 162.820 250.600 ;
      RECT 164.780 1.400 165.060 250.600 ;
      RECT 167.020 1.400 167.300 250.600 ;
      RECT 169.260 1.400 169.540 250.600 ;
      RECT 171.500 1.400 171.780 250.600 ;
      RECT 173.740 1.400 174.020 250.600 ;
      RECT 175.980 1.400 176.260 250.600 ;
      RECT 178.220 1.400 178.500 250.600 ;
    END
  END VSS
  PIN VDD
    DIRECTION INOUT ;
    USE POWER ;
    PORT
      LAYER metal4 ;
      RECT 2.380 1.400 2.660 250.600 ;
      RECT 4.620 1.400 4.900 250.600 ;
      RECT 6.860 1.400 7.140 250.600 ;
      RECT 9.100 1.400 9.380 250.600 ;
      RECT 11.340 1.400 11.620 250.600 ;
      RECT 13.580 1.400 13.860 250.600 ;
      RECT 15.820 1.400 16.100 250.600 ;
      RECT 18.060 1.400 18.340 250.600 ;
      RECT 20.300 1.400 20.580 250.600 ;
      RECT 22.540 1.400 22.820 250.600 ;
      RECT 24.780 1.400 25.060 250.600 ;
      RECT 27.020 1.400 27.300 250.600 ;
      RECT 29.260 1.400 29.540 250.600 ;
      RECT 31.500 1.400 31.780 250.600 ;
      RECT 33.740 1.400 34.020 250.600 ;
      RECT 35.980 1.400 36.260 250.600 ;
      RECT 38.220 1.400 38.500 250.600 ;
      RECT 40.460 1.400 40.740 250.600 ;
      RECT 42.700 1.400 42.980 250.600 ;
      RECT 44.940 1.400 45.220 250.600 ;
      RECT 47.180 1.400 47.460 250.600 ;
      RECT 49.420 1.400 49.700 250.600 ;
      RECT 51.660 1.400 51.940 250.600 ;
      RECT 53.900 1.400 54.180 250.600 ;
      RECT 56.140 1.400 56.420 250.600 ;
      RECT 58.380 1.400 58.660 250.600 ;
      RECT 60.620 1.400 60.900 250.600 ;
      RECT 62.860 1.400 63.140 250.600 ;
      RECT 65.100 1.400 65.380 250.600 ;
      RECT 67.340 1.400 67.620 250.600 ;
      RECT 69.580 1.400 69.860 250.600 ;
      RECT 71.820 1.400 72.100 250.600 ;
      RECT 74.060 1.400 74.340 250.600 ;
      RECT 76.300 1.400 76.580 250.600 ;
      RECT 78.540 1.400 78.820 250.600 ;
      RECT 80.780 1.400 81.060 250.600 ;
      RECT 83.020 1.400 83.300 250.600 ;
      RECT 85.260 1.400 85.540 250.600 ;
      RECT 87.500 1.400 87.780 250.600 ;
      RECT 89.740 1.400 90.020 250.600 ;
      RECT 91.980 1.400 92.260 250.600 ;
      RECT 94.220 1.400 94.500 250.600 ;
      RECT 96.460 1.400 96.740 250.600 ;
      RECT 98.700 1.400 98.980 250.600 ;
      RECT 100.940 1.400 101.220 250.600 ;
      RECT 103.180 1.400 103.460 250.600 ;
      RECT 105.420 1.400 105.700 250.600 ;
      RECT 107.660 1.400 107.940 250.600 ;
      RECT 109.900 1.400 110.180 250.600 ;
      RECT 112.140 1.400 112.420 250.600 ;
      RECT 114.380 1.400 114.660 250.600 ;
      RECT 116.620 1.400 116.900 250.600 ;
      RECT 118.860 1.400 119.140 250.600 ;
      RECT 121.100 1.400 121.380 250.600 ;
      RECT 123.340 1.400 123.620 250.600 ;
      RECT 125.580 1.400 125.860 250.600 ;
      RECT 127.820 1.400 128.100 250.600 ;
      RECT 130.060 1.400 130.340 250.600 ;
      RECT 132.300 1.400 132.580 250.600 ;
      RECT 134.540 1.400 134.820 250.600 ;
      RECT 136.780 1.400 137.060 250.600 ;
      RECT 139.020 1.400 139.300 250.600 ;
      RECT 141.260 1.400 141.540 250.600 ;
      RECT 143.500 1.400 143.780 250.600 ;
      RECT 145.740 1.400 146.020 250.600 ;
      RECT 147.980 1.400 148.260 250.600 ;
      RECT 150.220 1.400 150.500 250.600 ;
      RECT 152.460 1.400 152.740 250.600 ;
      RECT 154.700 1.400 154.980 250.600 ;
      RECT 156.940 1.400 157.220 250.600 ;
      RECT 159.180 1.400 159.460 250.600 ;
      RECT 161.420 1.400 161.700 250.600 ;
      RECT 163.660 1.400 163.940 250.600 ;
      RECT 165.900 1.400 166.180 250.600 ;
      RECT 168.140 1.400 168.420 250.600 ;
      RECT 170.380 1.400 170.660 250.600 ;
      RECT 172.620 1.400 172.900 250.600 ;
      RECT 174.860 1.400 175.140 250.600 ;
      RECT 177.100 1.400 177.380 250.600 ;
    END
  END VDD
  OBS
    LAYER metal1 ;
    RECT 0 0 180.120 252.000 ;
    LAYER metal2 ;
    RECT 0 0 180.120 252.000 ;
    LAYER metal3 ;
    RECT 0.070 0 180.120 252.000 ;
    RECT 0 0.000 0.070 1.365 ;
    RECT 0 1.435 0.070 1.925 ;
    RECT 0 1.995 0.070 2.485 ;
    RECT 0 2.555 0.070 3.045 ;
    RECT 0 3.115 0.070 3.605 ;
    RECT 0 3.675 0.070 4.165 ;
    RECT 0 4.235 0.070 4.725 ;
    RECT 0 4.795 0.070 5.285 ;
    RECT 0 5.355 0.070 5.845 ;
    RECT 0 5.915 0.070 6.405 ;
    RECT 0 6.475 0.070 6.965 ;
    RECT 0 7.035 0.070 7.525 ;
    RECT 0 7.595 0.070 8.085 ;
    RECT 0 8.155 0.070 8.645 ;
    RECT 0 8.715 0.070 9.205 ;
    RECT 0 9.275 0.070 9.765 ;
    RECT 0 9.835 0.070 10.325 ;
    RECT 0 10.395 0.070 10.885 ;
    RECT 0 10.955 0.070 11.445 ;
    RECT 0 11.515 0.070 12.005 ;
    RECT 0 12.075 0.070 12.565 ;
    RECT 0 12.635 0.070 13.125 ;
    RECT 0 13.195 0.070 13.685 ;
    RECT 0 13.755 0.070 14.245 ;
    RECT 0 14.315 0.070 14.805 ;
    RECT 0 14.875 0.070 15.365 ;
    RECT 0 15.435 0.070 15.925 ;
    RECT 0 15.995 0.070 16.485 ;
    RECT 0 16.555 0.070 17.045 ;
    RECT 0 17.115 0.070 17.605 ;
    RECT 0 17.675 0.070 18.165 ;
    RECT 0 18.235 0.070 18.725 ;
    RECT 0 18.795 0.070 19.285 ;
    RECT 0 19.355 0.070 19.845 ;
    RECT 0 19.915 0.070 20.405 ;
    RECT 0 20.475 0.070 20.965 ;
    RECT 0 21.035 0.070 21.525 ;
    RECT 0 21.595 0.070 22.085 ;
    RECT 0 22.155 0.070 22.645 ;
    RECT 0 22.715 0.070 23.205 ;
    RECT 0 23.275 0.070 23.765 ;
    RECT 0 23.835 0.070 24.325 ;
    RECT 0 24.395 0.070 24.885 ;
    RECT 0 24.955 0.070 25.445 ;
    RECT 0 25.515 0.070 26.005 ;
    RECT 0 26.075 0.070 26.565 ;
    RECT 0 26.635 0.070 27.125 ;
    RECT 0 27.195 0.070 27.685 ;
    RECT 0 27.755 0.070 28.245 ;
    RECT 0 28.315 0.070 28.805 ;
    RECT 0 28.875 0.070 29.365 ;
    RECT 0 29.435 0.070 29.925 ;
    RECT 0 29.995 0.070 30.485 ;
    RECT 0 30.555 0.070 31.045 ;
    RECT 0 31.115 0.070 31.605 ;
    RECT 0 31.675 0.070 32.165 ;
    RECT 0 32.235 0.070 32.725 ;
    RECT 0 32.795 0.070 33.285 ;
    RECT 0 33.355 0.070 33.845 ;
    RECT 0 33.915 0.070 34.405 ;
    RECT 0 34.475 0.070 34.965 ;
    RECT 0 35.035 0.070 35.525 ;
    RECT 0 35.595 0.070 36.085 ;
    RECT 0 36.155 0.070 36.645 ;
    RECT 0 36.715 0.070 37.205 ;
    RECT 0 37.275 0.070 37.765 ;
    RECT 0 37.835 0.070 38.325 ;
    RECT 0 38.395 0.070 38.885 ;
    RECT 0 38.955 0.070 39.445 ;
    RECT 0 39.515 0.070 40.005 ;
    RECT 0 40.075 0.070 40.565 ;
    RECT 0 40.635 0.070 41.125 ;
    RECT 0 41.195 0.070 41.685 ;
    RECT 0 41.755 0.070 42.245 ;
    RECT 0 42.315 0.070 42.805 ;
    RECT 0 42.875 0.070 43.365 ;
    RECT 0 43.435 0.070 43.925 ;
    RECT 0 43.995 0.070 44.485 ;
    RECT 0 44.555 0.070 45.045 ;
    RECT 0 45.115 0.070 45.605 ;
    RECT 0 45.675 0.070 46.165 ;
    RECT 0 46.235 0.070 46.725 ;
    RECT 0 46.795 0.070 47.285 ;
    RECT 0 47.355 0.070 47.845 ;
    RECT 0 47.915 0.070 48.405 ;
    RECT 0 48.475 0.070 48.965 ;
    RECT 0 49.035 0.070 49.525 ;
    RECT 0 49.595 0.070 50.085 ;
    RECT 0 50.155 0.070 50.645 ;
    RECT 0 50.715 0.070 51.205 ;
    RECT 0 51.275 0.070 51.765 ;
    RECT 0 51.835 0.070 52.325 ;
    RECT 0 52.395 0.070 52.885 ;
    RECT 0 52.955 0.070 53.445 ;
    RECT 0 53.515 0.070 54.005 ;
    RECT 0 54.075 0.070 54.565 ;
    RECT 0 54.635 0.070 55.125 ;
    RECT 0 55.195 0.070 55.685 ;
    RECT 0 55.755 0.070 56.245 ;
    RECT 0 56.315 0.070 56.805 ;
    RECT 0 56.875 0.070 57.365 ;
    RECT 0 57.435 0.070 57.925 ;
    RECT 0 57.995 0.070 58.485 ;
    RECT 0 58.555 0.070 59.045 ;
    RECT 0 59.115 0.070 59.605 ;
    RECT 0 59.675 0.070 60.165 ;
    RECT 0 60.235 0.070 60.725 ;
    RECT 0 60.795 0.070 61.285 ;
    RECT 0 61.355 0.070 61.845 ;
    RECT 0 61.915 0.070 62.405 ;
    RECT 0 62.475 0.070 62.965 ;
    RECT 0 63.035 0.070 63.525 ;
    RECT 0 63.595 0.070 64.085 ;
    RECT 0 64.155 0.070 64.645 ;
    RECT 0 64.715 0.070 65.205 ;
    RECT 0 65.275 0.070 65.765 ;
    RECT 0 65.835 0.070 66.325 ;
    RECT 0 66.395 0.070 66.885 ;
    RECT 0 66.955 0.070 67.445 ;
    RECT 0 67.515 0.070 68.005 ;
    RECT 0 68.075 0.070 68.565 ;
    RECT 0 68.635 0.070 69.125 ;
    RECT 0 69.195 0.070 69.685 ;
    RECT 0 69.755 0.070 70.245 ;
    RECT 0 70.315 0.070 70.805 ;
    RECT 0 70.875 0.070 71.365 ;
    RECT 0 71.435 0.070 71.925 ;
    RECT 0 71.995 0.070 72.485 ;
    RECT 0 72.555 0.070 73.045 ;
    RECT 0 73.115 0.070 73.605 ;
    RECT 0 73.675 0.070 74.165 ;
    RECT 0 74.235 0.070 74.725 ;
    RECT 0 74.795 0.070 75.285 ;
    RECT 0 75.355 0.070 75.845 ;
    RECT 0 75.915 0.070 76.405 ;
    RECT 0 76.475 0.070 76.965 ;
    RECT 0 77.035 0.070 77.525 ;
    RECT 0 77.595 0.070 78.085 ;
    RECT 0 78.155 0.070 78.645 ;
    RECT 0 78.715 0.070 79.205 ;
    RECT 0 79.275 0.070 79.765 ;
    RECT 0 79.835 0.070 80.325 ;
    RECT 0 80.395 0.070 80.885 ;
    RECT 0 80.955 0.070 81.445 ;
    RECT 0 81.515 0.070 82.005 ;
    RECT 0 82.075 0.070 82.565 ;
    RECT 0 82.635 0.070 83.125 ;
    RECT 0 83.195 0.070 83.685 ;
    RECT 0 83.755 0.070 84.245 ;
    RECT 0 84.315 0.070 84.805 ;
    RECT 0 84.875 0.070 85.365 ;
    RECT 0 85.435 0.070 85.925 ;
    RECT 0 85.995 0.070 86.485 ;
    RECT 0 86.555 0.070 87.045 ;
    RECT 0 87.115 0.070 87.605 ;
    RECT 0 87.675 0.070 88.165 ;
    RECT 0 88.235 0.070 88.725 ;
    RECT 0 88.795 0.070 89.285 ;
    RECT 0 89.355 0.070 89.845 ;
    RECT 0 89.915 0.070 90.405 ;
    RECT 0 90.475 0.070 90.965 ;
    RECT 0 91.035 0.070 91.525 ;
    RECT 0 91.595 0.070 92.085 ;
    RECT 0 92.155 0.070 92.645 ;
    RECT 0 92.715 0.070 93.205 ;
    RECT 0 93.275 0.070 93.765 ;
    RECT 0 93.835 0.070 94.325 ;
    RECT 0 94.395 0.070 94.885 ;
    RECT 0 94.955 0.070 95.445 ;
    RECT 0 95.515 0.070 96.005 ;
    RECT 0 96.075 0.070 96.565 ;
    RECT 0 96.635 0.070 97.125 ;
    RECT 0 97.195 0.070 97.685 ;
    RECT 0 97.755 0.070 98.245 ;
    RECT 0 98.315 0.070 98.805 ;
    RECT 0 98.875 0.070 99.365 ;
    RECT 0 99.435 0.070 99.925 ;
    RECT 0 99.995 0.070 100.485 ;
    RECT 0 100.555 0.070 101.045 ;
    RECT 0 101.115 0.070 101.605 ;
    RECT 0 101.675 0.070 102.165 ;
    RECT 0 102.235 0.070 102.725 ;
    RECT 0 102.795 0.070 103.285 ;
    RECT 0 103.355 0.070 103.845 ;
    RECT 0 103.915 0.070 104.405 ;
    RECT 0 104.475 0.070 104.965 ;
    RECT 0 105.035 0.070 105.525 ;
    RECT 0 105.595 0.070 106.085 ;
    RECT 0 106.155 0.070 106.645 ;
    RECT 0 106.715 0.070 107.205 ;
    RECT 0 107.275 0.070 107.765 ;
    RECT 0 107.835 0.070 108.325 ;
    RECT 0 108.395 0.070 108.885 ;
    RECT 0 108.955 0.070 109.445 ;
    RECT 0 109.515 0.070 110.005 ;
    RECT 0 110.075 0.070 110.565 ;
    RECT 0 110.635 0.070 111.125 ;
    RECT 0 111.195 0.070 111.685 ;
    RECT 0 111.755 0.070 112.245 ;
    RECT 0 112.315 0.070 112.805 ;
    RECT 0 112.875 0.070 113.365 ;
    RECT 0 113.435 0.070 113.925 ;
    RECT 0 113.995 0.070 114.485 ;
    RECT 0 114.555 0.070 115.045 ;
    RECT 0 115.115 0.070 115.605 ;
    RECT 0 115.675 0.070 116.165 ;
    RECT 0 116.235 0.070 116.725 ;
    RECT 0 116.795 0.070 117.285 ;
    RECT 0 117.355 0.070 117.845 ;
    RECT 0 117.915 0.070 118.405 ;
    RECT 0 118.475 0.070 118.965 ;
    RECT 0 119.035 0.070 119.525 ;
    RECT 0 119.595 0.070 120.085 ;
    RECT 0 120.155 0.070 120.645 ;
    RECT 0 120.715 0.070 121.205 ;
    RECT 0 121.275 0.070 121.765 ;
    RECT 0 121.835 0.070 122.325 ;
    RECT 0 122.395 0.070 122.885 ;
    RECT 0 122.955 0.070 123.445 ;
    RECT 0 123.515 0.070 124.005 ;
    RECT 0 124.075 0.070 124.565 ;
    RECT 0 124.635 0.070 125.125 ;
    RECT 0 125.195 0.070 125.685 ;
    RECT 0 125.755 0.070 126.245 ;
    RECT 0 126.315 0.070 126.805 ;
    RECT 0 126.875 0.070 127.365 ;
    RECT 0 127.435 0.070 127.925 ;
    RECT 0 127.995 0.070 128.485 ;
    RECT 0 128.555 0.070 129.045 ;
    RECT 0 129.115 0.070 129.605 ;
    RECT 0 129.675 0.070 130.165 ;
    RECT 0 130.235 0.070 130.725 ;
    RECT 0 130.795 0.070 131.285 ;
    RECT 0 131.355 0.070 131.845 ;
    RECT 0 131.915 0.070 132.405 ;
    RECT 0 132.475 0.070 132.965 ;
    RECT 0 133.035 0.070 133.525 ;
    RECT 0 133.595 0.070 134.085 ;
    RECT 0 134.155 0.070 134.645 ;
    RECT 0 134.715 0.070 135.205 ;
    RECT 0 135.275 0.070 135.765 ;
    RECT 0 135.835 0.070 136.325 ;
    RECT 0 136.395 0.070 136.885 ;
    RECT 0 136.955 0.070 137.445 ;
    RECT 0 137.515 0.070 138.005 ;
    RECT 0 138.075 0.070 138.565 ;
    RECT 0 138.635 0.070 139.125 ;
    RECT 0 139.195 0.070 139.685 ;
    RECT 0 139.755 0.070 140.245 ;
    RECT 0 140.315 0.070 140.805 ;
    RECT 0 140.875 0.070 141.365 ;
    RECT 0 141.435 0.070 141.925 ;
    RECT 0 141.995 0.070 142.485 ;
    RECT 0 142.555 0.070 143.045 ;
    RECT 0 143.115 0.070 143.605 ;
    RECT 0 143.675 0.070 144.165 ;
    RECT 0 144.235 0.070 144.725 ;
    RECT 0 144.795 0.070 145.285 ;
    RECT 0 145.355 0.070 145.845 ;
    RECT 0 145.915 0.070 146.405 ;
    RECT 0 146.475 0.070 146.965 ;
    RECT 0 147.035 0.070 147.525 ;
    RECT 0 147.595 0.070 148.085 ;
    RECT 0 148.155 0.070 148.645 ;
    RECT 0 148.715 0.070 156.625 ;
    RECT 0 156.695 0.070 157.185 ;
    RECT 0 157.255 0.070 157.745 ;
    RECT 0 157.815 0.070 158.305 ;
    RECT 0 158.375 0.070 158.865 ;
    RECT 0 158.935 0.070 159.425 ;
    RECT 0 159.495 0.070 159.985 ;
    RECT 0 160.055 0.070 160.545 ;
    RECT 0 160.615 0.070 161.105 ;
    RECT 0 161.175 0.070 161.665 ;
    RECT 0 161.735 0.070 162.225 ;
    RECT 0 162.295 0.070 162.785 ;
    RECT 0 162.855 0.070 163.345 ;
    RECT 0 163.415 0.070 163.905 ;
    RECT 0 163.975 0.070 164.465 ;
    RECT 0 164.535 0.070 165.025 ;
    RECT 0 165.095 0.070 165.585 ;
    RECT 0 165.655 0.070 166.145 ;
    RECT 0 166.215 0.070 166.705 ;
    RECT 0 166.775 0.070 167.265 ;
    RECT 0 167.335 0.070 167.825 ;
    RECT 0 167.895 0.070 168.385 ;
    RECT 0 168.455 0.070 168.945 ;
    RECT 0 169.015 0.070 169.505 ;
    RECT 0 169.575 0.070 170.065 ;
    RECT 0 170.135 0.070 170.625 ;
    RECT 0 170.695 0.070 171.185 ;
    RECT 0 171.255 0.070 171.745 ;
    RECT 0 171.815 0.070 172.305 ;
    RECT 0 172.375 0.070 172.865 ;
    RECT 0 172.935 0.070 173.425 ;
    RECT 0 173.495 0.070 173.985 ;
    RECT 0 174.055 0.070 174.545 ;
    RECT 0 174.615 0.070 175.105 ;
    RECT 0 175.175 0.070 175.665 ;
    RECT 0 175.735 0.070 176.225 ;
    RECT 0 176.295 0.070 176.785 ;
    RECT 0 176.855 0.070 177.345 ;
    RECT 0 177.415 0.070 177.905 ;
    RECT 0 177.975 0.070 178.465 ;
    RECT 0 178.535 0.070 179.025 ;
    RECT 0 179.095 0.070 179.585 ;
    RECT 0 179.655 0.070 180.145 ;
    RECT 0 180.215 0.070 180.705 ;
    RECT 0 180.775 0.070 181.265 ;
    RECT 0 181.335 0.070 181.825 ;
    RECT 0 181.895 0.070 182.385 ;
    RECT 0 182.455 0.070 182.945 ;
    RECT 0 183.015 0.070 183.505 ;
    RECT 0 183.575 0.070 184.065 ;
    RECT 0 184.135 0.070 184.625 ;
    RECT 0 184.695 0.070 185.185 ;
    RECT 0 185.255 0.070 185.745 ;
    RECT 0 185.815 0.070 186.305 ;
    RECT 0 186.375 0.070 186.865 ;
    RECT 0 186.935 0.070 187.425 ;
    RECT 0 187.495 0.070 187.985 ;
    RECT 0 188.055 0.070 188.545 ;
    RECT 0 188.615 0.070 189.105 ;
    RECT 0 189.175 0.070 189.665 ;
    RECT 0 189.735 0.070 190.225 ;
    RECT 0 190.295 0.070 190.785 ;
    RECT 0 190.855 0.070 191.345 ;
    RECT 0 191.415 0.070 191.905 ;
    RECT 0 191.975 0.070 192.465 ;
    RECT 0 192.535 0.070 193.025 ;
    RECT 0 193.095 0.070 193.585 ;
    RECT 0 193.655 0.070 194.145 ;
    RECT 0 194.215 0.070 194.705 ;
    RECT 0 194.775 0.070 195.265 ;
    RECT 0 195.335 0.070 195.825 ;
    RECT 0 195.895 0.070 196.385 ;
    RECT 0 196.455 0.070 196.945 ;
    RECT 0 197.015 0.070 197.505 ;
    RECT 0 197.575 0.070 198.065 ;
    RECT 0 198.135 0.070 198.625 ;
    RECT 0 198.695 0.070 199.185 ;
    RECT 0 199.255 0.070 199.745 ;
    RECT 0 199.815 0.070 200.305 ;
    RECT 0 200.375 0.070 200.865 ;
    RECT 0 200.935 0.070 201.425 ;
    RECT 0 201.495 0.070 201.985 ;
    RECT 0 202.055 0.070 202.545 ;
    RECT 0 202.615 0.070 203.105 ;
    RECT 0 203.175 0.070 203.665 ;
    RECT 0 203.735 0.070 204.225 ;
    RECT 0 204.295 0.070 204.785 ;
    RECT 0 204.855 0.070 205.345 ;
    RECT 0 205.415 0.070 205.905 ;
    RECT 0 205.975 0.070 206.465 ;
    RECT 0 206.535 0.070 207.025 ;
    RECT 0 207.095 0.070 207.585 ;
    RECT 0 207.655 0.070 208.145 ;
    RECT 0 208.215 0.070 208.705 ;
    RECT 0 208.775 0.070 209.265 ;
    RECT 0 209.335 0.070 209.825 ;
    RECT 0 209.895 0.070 210.385 ;
    RECT 0 210.455 0.070 210.945 ;
    RECT 0 211.015 0.070 211.505 ;
    RECT 0 211.575 0.070 212.065 ;
    RECT 0 212.135 0.070 212.625 ;
    RECT 0 212.695 0.070 213.185 ;
    RECT 0 213.255 0.070 213.745 ;
    RECT 0 213.815 0.070 214.305 ;
    RECT 0 214.375 0.070 214.865 ;
    RECT 0 214.935 0.070 215.425 ;
    RECT 0 215.495 0.070 215.985 ;
    RECT 0 216.055 0.070 216.545 ;
    RECT 0 216.615 0.070 217.105 ;
    RECT 0 217.175 0.070 217.665 ;
    RECT 0 217.735 0.070 218.225 ;
    RECT 0 218.295 0.070 218.785 ;
    RECT 0 218.855 0.070 219.345 ;
    RECT 0 219.415 0.070 219.905 ;
    RECT 0 219.975 0.070 220.465 ;
    RECT 0 220.535 0.070 221.025 ;
    RECT 0 221.095 0.070 221.585 ;
    RECT 0 221.655 0.070 222.145 ;
    RECT 0 222.215 0.070 222.705 ;
    RECT 0 222.775 0.070 223.265 ;
    RECT 0 223.335 0.070 223.825 ;
    RECT 0 223.895 0.070 224.385 ;
    RECT 0 224.455 0.070 224.945 ;
    RECT 0 225.015 0.070 225.505 ;
    RECT 0 225.575 0.070 226.065 ;
    RECT 0 226.135 0.070 226.625 ;
    RECT 0 226.695 0.070 227.185 ;
    RECT 0 227.255 0.070 227.745 ;
    RECT 0 227.815 0.070 228.305 ;
    RECT 0 228.375 0.070 228.865 ;
    RECT 0 228.935 0.070 229.425 ;
    RECT 0 229.495 0.070 229.985 ;
    RECT 0 230.055 0.070 230.545 ;
    RECT 0 230.615 0.070 231.105 ;
    RECT 0 231.175 0.070 231.665 ;
    RECT 0 231.735 0.070 232.225 ;
    RECT 0 232.295 0.070 240.205 ;
    RECT 0 240.275 0.070 252.000 ;
    LAYER metal4 ;
    RECT 0 0 180.120 1.400 ;
    RECT 0 250.600 180.120 252.000 ;
    RECT 0.000 1.400 1.260 250.600 ;
    RECT 1.540 1.400 2.380 250.600 ;
    RECT 2.660 1.400 3.500 250.600 ;
    RECT 3.780 1.400 4.620 250.600 ;
    RECT 4.900 1.400 5.740 250.600 ;
    RECT 6.020 1.400 6.860 250.600 ;
    RECT 7.140 1.400 7.980 250.600 ;
    RECT 8.260 1.400 9.100 250.600 ;
    RECT 9.380 1.400 10.220 250.600 ;
    RECT 10.500 1.400 11.340 250.600 ;
    RECT 11.620 1.400 12.460 250.600 ;
    RECT 12.740 1.400 13.580 250.600 ;
    RECT 13.860 1.400 14.700 250.600 ;
    RECT 14.980 1.400 15.820 250.600 ;
    RECT 16.100 1.400 16.940 250.600 ;
    RECT 17.220 1.400 18.060 250.600 ;
    RECT 18.340 1.400 19.180 250.600 ;
    RECT 19.460 1.400 20.300 250.600 ;
    RECT 20.580 1.400 21.420 250.600 ;
    RECT 21.700 1.400 22.540 250.600 ;
    RECT 22.820 1.400 23.660 250.600 ;
    RECT 23.940 1.400 24.780 250.600 ;
    RECT 25.060 1.400 25.900 250.600 ;
    RECT 26.180 1.400 27.020 250.600 ;
    RECT 27.300 1.400 28.140 250.600 ;
    RECT 28.420 1.400 29.260 250.600 ;
    RECT 29.540 1.400 30.380 250.600 ;
    RECT 30.660 1.400 31.500 250.600 ;
    RECT 31.780 1.400 32.620 250.600 ;
    RECT 32.900 1.400 33.740 250.600 ;
    RECT 34.020 1.400 34.860 250.600 ;
    RECT 35.140 1.400 35.980 250.600 ;
    RECT 36.260 1.400 37.100 250.600 ;
    RECT 37.380 1.400 38.220 250.600 ;
    RECT 38.500 1.400 39.340 250.600 ;
    RECT 39.620 1.400 40.460 250.600 ;
    RECT 40.740 1.400 41.580 250.600 ;
    RECT 41.860 1.400 42.700 250.600 ;
    RECT 42.980 1.400 43.820 250.600 ;
    RECT 44.100 1.400 44.940 250.600 ;
    RECT 45.220 1.400 46.060 250.600 ;
    RECT 46.340 1.400 47.180 250.600 ;
    RECT 47.460 1.400 48.300 250.600 ;
    RECT 48.580 1.400 49.420 250.600 ;
    RECT 49.700 1.400 50.540 250.600 ;
    RECT 50.820 1.400 51.660 250.600 ;
    RECT 51.940 1.400 52.780 250.600 ;
    RECT 53.060 1.400 53.900 250.600 ;
    RECT 54.180 1.400 55.020 250.600 ;
    RECT 55.300 1.400 56.140 250.600 ;
    RECT 56.420 1.400 57.260 250.600 ;
    RECT 57.540 1.400 58.380 250.600 ;
    RECT 58.660 1.400 59.500 250.600 ;
    RECT 59.780 1.400 60.620 250.600 ;
    RECT 60.900 1.400 61.740 250.600 ;
    RECT 62.020 1.400 62.860 250.600 ;
    RECT 63.140 1.400 63.980 250.600 ;
    RECT 64.260 1.400 65.100 250.600 ;
    RECT 65.380 1.400 66.220 250.600 ;
    RECT 66.500 1.400 67.340 250.600 ;
    RECT 67.620 1.400 68.460 250.600 ;
    RECT 68.740 1.400 69.580 250.600 ;
    RECT 69.860 1.400 70.700 250.600 ;
    RECT 70.980 1.400 71.820 250.600 ;
    RECT 72.100 1.400 72.940 250.600 ;
    RECT 73.220 1.400 74.060 250.600 ;
    RECT 74.340 1.400 75.180 250.600 ;
    RECT 75.460 1.400 76.300 250.600 ;
    RECT 76.580 1.400 77.420 250.600 ;
    RECT 77.700 1.400 78.540 250.600 ;
    RECT 78.820 1.400 79.660 250.600 ;
    RECT 79.940 1.400 80.780 250.600 ;
    RECT 81.060 1.400 81.900 250.600 ;
    RECT 82.180 1.400 83.020 250.600 ;
    RECT 83.300 1.400 84.140 250.600 ;
    RECT 84.420 1.400 85.260 250.600 ;
    RECT 85.540 1.400 86.380 250.600 ;
    RECT 86.660 1.400 87.500 250.600 ;
    RECT 87.780 1.400 88.620 250.600 ;
    RECT 88.900 1.400 89.740 250.600 ;
    RECT 90.020 1.400 90.860 250.600 ;
    RECT 91.140 1.400 91.980 250.600 ;
    RECT 92.260 1.400 93.100 250.600 ;
    RECT 93.380 1.400 94.220 250.600 ;
    RECT 94.500 1.400 95.340 250.600 ;
    RECT 95.620 1.400 96.460 250.600 ;
    RECT 96.740 1.400 97.580 250.600 ;
    RECT 97.860 1.400 98.700 250.600 ;
    RECT 98.980 1.400 99.820 250.600 ;
    RECT 100.100 1.400 100.940 250.600 ;
    RECT 101.220 1.400 102.060 250.600 ;
    RECT 102.340 1.400 103.180 250.600 ;
    RECT 103.460 1.400 104.300 250.600 ;
    RECT 104.580 1.400 105.420 250.600 ;
    RECT 105.700 1.400 106.540 250.600 ;
    RECT 106.820 1.400 107.660 250.600 ;
    RECT 107.940 1.400 108.780 250.600 ;
    RECT 109.060 1.400 109.900 250.600 ;
    RECT 110.180 1.400 111.020 250.600 ;
    RECT 111.300 1.400 112.140 250.600 ;
    RECT 112.420 1.400 113.260 250.600 ;
    RECT 113.540 1.400 114.380 250.600 ;
    RECT 114.660 1.400 115.500 250.600 ;
    RECT 115.780 1.400 116.620 250.600 ;
    RECT 116.900 1.400 117.740 250.600 ;
    RECT 118.020 1.400 118.860 250.600 ;
    RECT 119.140 1.400 119.980 250.600 ;
    RECT 120.260 1.400 121.100 250.600 ;
    RECT 121.380 1.400 122.220 250.600 ;
    RECT 122.500 1.400 123.340 250.600 ;
    RECT 123.620 1.400 124.460 250.600 ;
    RECT 124.740 1.400 125.580 250.600 ;
    RECT 125.860 1.400 126.700 250.600 ;
    RECT 126.980 1.400 127.820 250.600 ;
    RECT 128.100 1.400 128.940 250.600 ;
    RECT 129.220 1.400 130.060 250.600 ;
    RECT 130.340 1.400 131.180 250.600 ;
    RECT 131.460 1.400 132.300 250.600 ;
    RECT 132.580 1.400 133.420 250.600 ;
    RECT 133.700 1.400 134.540 250.600 ;
    RECT 134.820 1.400 135.660 250.600 ;
    RECT 135.940 1.400 136.780 250.600 ;
    RECT 137.060 1.400 137.900 250.600 ;
    RECT 138.180 1.400 139.020 250.600 ;
    RECT 139.300 1.400 140.140 250.600 ;
    RECT 140.420 1.400 141.260 250.600 ;
    RECT 141.540 1.400 142.380 250.600 ;
    RECT 142.660 1.400 143.500 250.600 ;
    RECT 143.780 1.400 144.620 250.600 ;
    RECT 144.900 1.400 145.740 250.600 ;
    RECT 146.020 1.400 146.860 250.600 ;
    RECT 147.140 1.400 147.980 250.600 ;
    RECT 148.260 1.400 149.100 250.600 ;
    RECT 149.380 1.400 150.220 250.600 ;
    RECT 150.500 1.400 151.340 250.600 ;
    RECT 151.620 1.400 152.460 250.600 ;
    RECT 152.740 1.400 153.580 250.600 ;
    RECT 153.860 1.400 154.700 250.600 ;
    RECT 154.980 1.400 155.820 250.600 ;
    RECT 156.100 1.400 156.940 250.600 ;
    RECT 157.220 1.400 158.060 250.600 ;
    RECT 158.340 1.400 159.180 250.600 ;
    RECT 159.460 1.400 160.300 250.600 ;
    RECT 160.580 1.400 161.420 250.600 ;
    RECT 161.700 1.400 162.540 250.600 ;
    RECT 162.820 1.400 163.660 250.600 ;
    RECT 163.940 1.400 164.780 250.600 ;
    RECT 165.060 1.400 165.900 250.600 ;
    RECT 166.180 1.400 167.020 250.600 ;
    RECT 167.300 1.400 168.140 250.600 ;
    RECT 168.420 1.400 169.260 250.600 ;
    RECT 169.540 1.400 170.380 250.600 ;
    RECT 170.660 1.400 171.500 250.600 ;
    RECT 171.780 1.400 172.620 250.600 ;
    RECT 172.900 1.400 173.740 250.600 ;
    RECT 174.020 1.400 174.860 250.600 ;
    RECT 175.140 1.400 175.980 250.600 ;
    RECT 176.260 1.400 177.100 250.600 ;
    RECT 177.380 1.400 178.220 250.600 ;
    RECT 178.500 1.400 180.120 250.600 ;
    LAYER OVERLAP ;
    RECT 0 0 180.120 252.000 ;
  END
END sram_128x128_1r1w

END LIBRARY
